VERSION 5.8 ;
BUSBITCHARS "[]" ;
DIVIDERCHAR "/" ;
UNITS
    DATABASE MICRONS 1000 ;
END UNITS

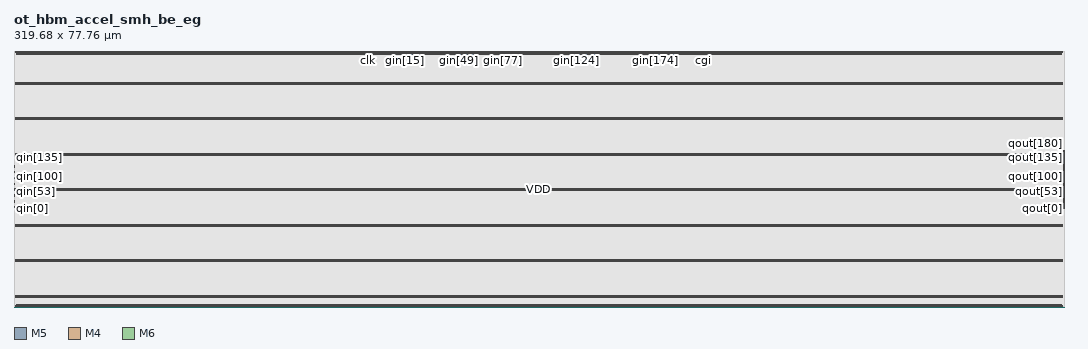
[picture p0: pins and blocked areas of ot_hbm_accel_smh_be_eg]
MACRO ot_hbm_accel_smh_be_eg
  FOREIGN ot_hbm_accel_smh_be_eg 0 0 ;
  CLASS BLOCK ;
  SIZE 319.68 BY 77.76 ;
  PIN cgi
    DIRECTION INPUT ;
    USE SIGNAL ;
    PORT
      LAYER M5 ;
        RECT  209.856 77.568 209.88 77.76 ;
    END
  END cgi
  PIN cgo
    DIRECTION OUTPUT ;
    USE SIGNAL ;
    PORT
      LAYER M5 ;
        RECT  210.336 77.568 210.36 77.76 ;
    END
  END cgo
  PIN clk
    DIRECTION INPUT ;
    USE SIGNAL ;
    PORT
      LAYER M5 ;
        RECT  107.856 77.568 107.88 77.76 ;
    END
  END clk
  PIN gin[0]
    DIRECTION INPUT ;
    USE SIGNAL ;
    PORT
      LAYER M5 ;
        RECT  111.84 77.568 111.864 77.76 ;
    END
  END gin[0]
  PIN gin[100]
    DIRECTION INPUT ;
    USE SIGNAL ;
    PORT
      LAYER M5 ;
        RECT  159.84 77.568 159.864 77.76 ;
    END
  END gin[100]
  PIN gin[101]
    DIRECTION INPUT ;
    USE SIGNAL ;
    PORT
      LAYER M5 ;
        RECT  160.32 77.568 160.344 77.76 ;
    END
  END gin[101]
  PIN gin[102]
    DIRECTION INPUT ;
    USE SIGNAL ;
    PORT
      LAYER M5 ;
        RECT  160.8 77.568 160.824 77.76 ;
    END
  END gin[102]
  PIN gin[103]
    DIRECTION INPUT ;
    USE SIGNAL ;
    PORT
      LAYER M5 ;
        RECT  161.28 77.568 161.304 77.76 ;
    END
  END gin[103]
  PIN gin[104]
    DIRECTION INPUT ;
    USE SIGNAL ;
    PORT
      LAYER M5 ;
        RECT  161.76 77.568 161.784 77.76 ;
    END
  END gin[104]
  PIN gin[105]
    DIRECTION INPUT ;
    USE SIGNAL ;
    PORT
      LAYER M5 ;
        RECT  162.24 77.568 162.264 77.76 ;
    END
  END gin[105]
  PIN gin[106]
    DIRECTION INPUT ;
    USE SIGNAL ;
    PORT
      LAYER M5 ;
        RECT  162.72 77.568 162.744 77.76 ;
    END
  END gin[106]
  PIN gin[107]
    DIRECTION INPUT ;
    USE SIGNAL ;
    PORT
      LAYER M5 ;
        RECT  163.2 77.568 163.224 77.76 ;
    END
  END gin[107]
  PIN gin[108]
    DIRECTION INPUT ;
    USE SIGNAL ;
    PORT
      LAYER M5 ;
        RECT  163.68 77.568 163.704 77.76 ;
    END
  END gin[108]
  PIN gin[109]
    DIRECTION INPUT ;
    USE SIGNAL ;
    PORT
      LAYER M5 ;
        RECT  164.16 77.568 164.184 77.76 ;
    END
  END gin[109]
  PIN gin[10]
    DIRECTION INPUT ;
    USE SIGNAL ;
    PORT
      LAYER M5 ;
        RECT  116.64 77.568 116.664 77.76 ;
    END
  END gin[10]
  PIN gin[110]
    DIRECTION INPUT ;
    USE SIGNAL ;
    PORT
      LAYER M5 ;
        RECT  164.64 77.568 164.664 77.76 ;
    END
  END gin[110]
  PIN gin[111]
    DIRECTION INPUT ;
    USE SIGNAL ;
    PORT
      LAYER M5 ;
        RECT  165.12 77.568 165.144 77.76 ;
    END
  END gin[111]
  PIN gin[112]
    DIRECTION INPUT ;
    USE SIGNAL ;
    PORT
      LAYER M5 ;
        RECT  165.6 77.568 165.624 77.76 ;
    END
  END gin[112]
  PIN gin[113]
    DIRECTION INPUT ;
    USE SIGNAL ;
    PORT
      LAYER M5 ;
        RECT  166.08 77.568 166.104 77.76 ;
    END
  END gin[113]
  PIN gin[114]
    DIRECTION INPUT ;
    USE SIGNAL ;
    PORT
      LAYER M5 ;
        RECT  166.56 77.568 166.584 77.76 ;
    END
  END gin[114]
  PIN gin[115]
    DIRECTION INPUT ;
    USE SIGNAL ;
    PORT
      LAYER M5 ;
        RECT  167.04 77.568 167.064 77.76 ;
    END
  END gin[115]
  PIN gin[116]
    DIRECTION INPUT ;
    USE SIGNAL ;
    PORT
      LAYER M5 ;
        RECT  167.52 77.568 167.544 77.76 ;
    END
  END gin[116]
  PIN gin[117]
    DIRECTION INPUT ;
    USE SIGNAL ;
    PORT
      LAYER M5 ;
        RECT  168 77.568 168.024 77.76 ;
    END
  END gin[117]
  PIN gin[118]
    DIRECTION INPUT ;
    USE SIGNAL ;
    PORT
      LAYER M5 ;
        RECT  168.48 77.568 168.504 77.76 ;
    END
  END gin[118]
  PIN gin[119]
    DIRECTION INPUT ;
    USE SIGNAL ;
    PORT
      LAYER M5 ;
        RECT  168.96 77.568 168.984 77.76 ;
    END
  END gin[119]
  PIN gin[11]
    DIRECTION INPUT ;
    USE SIGNAL ;
    PORT
      LAYER M5 ;
        RECT  117.12 77.568 117.144 77.76 ;
    END
  END gin[11]
  PIN gin[120]
    DIRECTION INPUT ;
    USE SIGNAL ;
    PORT
      LAYER M5 ;
        RECT  169.44 77.568 169.464 77.76 ;
    END
  END gin[120]
  PIN gin[121]
    DIRECTION INPUT ;
    USE SIGNAL ;
    PORT
      LAYER M5 ;
        RECT  169.92 77.568 169.944 77.76 ;
    END
  END gin[121]
  PIN gin[122]
    DIRECTION INPUT ;
    USE SIGNAL ;
    PORT
      LAYER M5 ;
        RECT  170.4 77.568 170.424 77.76 ;
    END
  END gin[122]
  PIN gin[123]
    DIRECTION INPUT ;
    USE SIGNAL ;
    PORT
      LAYER M5 ;
        RECT  170.88 77.568 170.904 77.76 ;
    END
  END gin[123]
  PIN gin[124]
    DIRECTION INPUT ;
    USE SIGNAL ;
    PORT
      LAYER M5 ;
        RECT  171.36 77.568 171.384 77.76 ;
    END
  END gin[124]
  PIN gin[125]
    DIRECTION INPUT ;
    USE SIGNAL ;
    PORT
      LAYER M5 ;
        RECT  171.84 77.568 171.864 77.76 ;
    END
  END gin[125]
  PIN gin[126]
    DIRECTION INPUT ;
    USE SIGNAL ;
    PORT
      LAYER M5 ;
        RECT  172.32 77.568 172.344 77.76 ;
    END
  END gin[126]
  PIN gin[127]
    DIRECTION INPUT ;
    USE SIGNAL ;
    PORT
      LAYER M5 ;
        RECT  172.8 77.568 172.824 77.76 ;
    END
  END gin[127]
  PIN gin[128]
    DIRECTION INPUT ;
    USE SIGNAL ;
    PORT
      LAYER M5 ;
        RECT  173.28 77.568 173.304 77.76 ;
    END
  END gin[128]
  PIN gin[129]
    DIRECTION INPUT ;
    USE SIGNAL ;
    PORT
      LAYER M5 ;
        RECT  173.76 77.568 173.784 77.76 ;
    END
  END gin[129]
  PIN gin[12]
    DIRECTION INPUT ;
    USE SIGNAL ;
    PORT
      LAYER M5 ;
        RECT  117.6 77.568 117.624 77.76 ;
    END
  END gin[12]
  PIN gin[130]
    DIRECTION INPUT ;
    USE SIGNAL ;
    PORT
      LAYER M5 ;
        RECT  174.24 77.568 174.264 77.76 ;
    END
  END gin[130]
  PIN gin[131]
    DIRECTION INPUT ;
    USE SIGNAL ;
    PORT
      LAYER M5 ;
        RECT  174.72 77.568 174.744 77.76 ;
    END
  END gin[131]
  PIN gin[132]
    DIRECTION INPUT ;
    USE SIGNAL ;
    PORT
      LAYER M5 ;
        RECT  175.2 77.568 175.224 77.76 ;
    END
  END gin[132]
  PIN gin[133]
    DIRECTION INPUT ;
    USE SIGNAL ;
    PORT
      LAYER M5 ;
        RECT  175.68 77.568 175.704 77.76 ;
    END
  END gin[133]
  PIN gin[134]
    DIRECTION INPUT ;
    USE SIGNAL ;
    PORT
      LAYER M5 ;
        RECT  176.16 77.568 176.184 77.76 ;
    END
  END gin[134]
  PIN gin[135]
    DIRECTION INPUT ;
    USE SIGNAL ;
    PORT
      LAYER M5 ;
        RECT  176.64 77.568 176.664 77.76 ;
    END
  END gin[135]
  PIN gin[136]
    DIRECTION INPUT ;
    USE SIGNAL ;
    PORT
      LAYER M5 ;
        RECT  177.12 77.568 177.144 77.76 ;
    END
  END gin[136]
  PIN gin[137]
    DIRECTION INPUT ;
    USE SIGNAL ;
    PORT
      LAYER M5 ;
        RECT  177.6 77.568 177.624 77.76 ;
    END
  END gin[137]
  PIN gin[138]
    DIRECTION INPUT ;
    USE SIGNAL ;
    PORT
      LAYER M5 ;
        RECT  178.08 77.568 178.104 77.76 ;
    END
  END gin[138]
  PIN gin[139]
    DIRECTION INPUT ;
    USE SIGNAL ;
    PORT
      LAYER M5 ;
        RECT  178.56 77.568 178.584 77.76 ;
    END
  END gin[139]
  PIN gin[13]
    DIRECTION INPUT ;
    USE SIGNAL ;
    PORT
      LAYER M5 ;
        RECT  118.08 77.568 118.104 77.76 ;
    END
  END gin[13]
  PIN gin[140]
    DIRECTION INPUT ;
    USE SIGNAL ;
    PORT
      LAYER M5 ;
        RECT  179.04 77.568 179.064 77.76 ;
    END
  END gin[140]
  PIN gin[141]
    DIRECTION INPUT ;
    USE SIGNAL ;
    PORT
      LAYER M5 ;
        RECT  179.52 77.568 179.544 77.76 ;
    END
  END gin[141]
  PIN gin[142]
    DIRECTION INPUT ;
    USE SIGNAL ;
    PORT
      LAYER M5 ;
        RECT  180 77.568 180.024 77.76 ;
    END
  END gin[142]
  PIN gin[143]
    DIRECTION INPUT ;
    USE SIGNAL ;
    PORT
      LAYER M5 ;
        RECT  180.48 77.568 180.504 77.76 ;
    END
  END gin[143]
  PIN gin[144]
    DIRECTION INPUT ;
    USE SIGNAL ;
    PORT
      LAYER M5 ;
        RECT  180.96 77.568 180.984 77.76 ;
    END
  END gin[144]
  PIN gin[145]
    DIRECTION INPUT ;
    USE SIGNAL ;
    PORT
      LAYER M5 ;
        RECT  181.44 77.568 181.464 77.76 ;
    END
  END gin[145]
  PIN gin[146]
    DIRECTION INPUT ;
    USE SIGNAL ;
    PORT
      LAYER M5 ;
        RECT  181.92 77.568 181.944 77.76 ;
    END
  END gin[146]
  PIN gin[147]
    DIRECTION INPUT ;
    USE SIGNAL ;
    PORT
      LAYER M5 ;
        RECT  182.4 77.568 182.424 77.76 ;
    END
  END gin[147]
  PIN gin[148]
    DIRECTION INPUT ;
    USE SIGNAL ;
    PORT
      LAYER M5 ;
        RECT  182.88 77.568 182.904 77.76 ;
    END
  END gin[148]
  PIN gin[149]
    DIRECTION INPUT ;
    USE SIGNAL ;
    PORT
      LAYER M5 ;
        RECT  183.36 77.568 183.384 77.76 ;
    END
  END gin[149]
  PIN gin[14]
    DIRECTION INPUT ;
    USE SIGNAL ;
    PORT
      LAYER M5 ;
        RECT  118.56 77.568 118.584 77.76 ;
    END
  END gin[14]
  PIN gin[150]
    DIRECTION INPUT ;
    USE SIGNAL ;
    PORT
      LAYER M5 ;
        RECT  183.84 77.568 183.864 77.76 ;
    END
  END gin[150]
  PIN gin[151]
    DIRECTION INPUT ;
    USE SIGNAL ;
    PORT
      LAYER M5 ;
        RECT  184.32 77.568 184.344 77.76 ;
    END
  END gin[151]
  PIN gin[152]
    DIRECTION INPUT ;
    USE SIGNAL ;
    PORT
      LAYER M5 ;
        RECT  184.8 77.568 184.824 77.76 ;
    END
  END gin[152]
  PIN gin[153]
    DIRECTION INPUT ;
    USE SIGNAL ;
    PORT
      LAYER M5 ;
        RECT  185.28 77.568 185.304 77.76 ;
    END
  END gin[153]
  PIN gin[154]
    DIRECTION INPUT ;
    USE SIGNAL ;
    PORT
      LAYER M5 ;
        RECT  185.76 77.568 185.784 77.76 ;
    END
  END gin[154]
  PIN gin[155]
    DIRECTION INPUT ;
    USE SIGNAL ;
    PORT
      LAYER M5 ;
        RECT  186.24 77.568 186.264 77.76 ;
    END
  END gin[155]
  PIN gin[156]
    DIRECTION INPUT ;
    USE SIGNAL ;
    PORT
      LAYER M5 ;
        RECT  186.72 77.568 186.744 77.76 ;
    END
  END gin[156]
  PIN gin[157]
    DIRECTION INPUT ;
    USE SIGNAL ;
    PORT
      LAYER M5 ;
        RECT  187.2 77.568 187.224 77.76 ;
    END
  END gin[157]
  PIN gin[158]
    DIRECTION INPUT ;
    USE SIGNAL ;
    PORT
      LAYER M5 ;
        RECT  187.68 77.568 187.704 77.76 ;
    END
  END gin[158]
  PIN gin[159]
    DIRECTION INPUT ;
    USE SIGNAL ;
    PORT
      LAYER M5 ;
        RECT  188.16 77.568 188.184 77.76 ;
    END
  END gin[159]
  PIN gin[15]
    DIRECTION INPUT ;
    USE SIGNAL ;
    PORT
      LAYER M5 ;
        RECT  119.04 77.568 119.064 77.76 ;
    END
  END gin[15]
  PIN gin[160]
    DIRECTION INPUT ;
    USE SIGNAL ;
    PORT
      LAYER M5 ;
        RECT  188.64 77.568 188.664 77.76 ;
    END
  END gin[160]
  PIN gin[161]
    DIRECTION INPUT ;
    USE SIGNAL ;
    PORT
      LAYER M5 ;
        RECT  189.12 77.568 189.144 77.76 ;
    END
  END gin[161]
  PIN gin[162]
    DIRECTION INPUT ;
    USE SIGNAL ;
    PORT
      LAYER M5 ;
        RECT  189.6 77.568 189.624 77.76 ;
    END
  END gin[162]
  PIN gin[163]
    DIRECTION INPUT ;
    USE SIGNAL ;
    PORT
      LAYER M5 ;
        RECT  190.08 77.568 190.104 77.76 ;
    END
  END gin[163]
  PIN gin[164]
    DIRECTION INPUT ;
    USE SIGNAL ;
    PORT
      LAYER M5 ;
        RECT  190.56 77.568 190.584 77.76 ;
    END
  END gin[164]
  PIN gin[165]
    DIRECTION INPUT ;
    USE SIGNAL ;
    PORT
      LAYER M5 ;
        RECT  191.04 77.568 191.064 77.76 ;
    END
  END gin[165]
  PIN gin[166]
    DIRECTION INPUT ;
    USE SIGNAL ;
    PORT
      LAYER M5 ;
        RECT  191.52 77.568 191.544 77.76 ;
    END
  END gin[166]
  PIN gin[167]
    DIRECTION INPUT ;
    USE SIGNAL ;
    PORT
      LAYER M5 ;
        RECT  192 77.568 192.024 77.76 ;
    END
  END gin[167]
  PIN gin[168]
    DIRECTION INPUT ;
    USE SIGNAL ;
    PORT
      LAYER M5 ;
        RECT  192.48 77.568 192.504 77.76 ;
    END
  END gin[168]
  PIN gin[169]
    DIRECTION INPUT ;
    USE SIGNAL ;
    PORT
      LAYER M5 ;
        RECT  192.96 77.568 192.984 77.76 ;
    END
  END gin[169]
  PIN gin[16]
    DIRECTION INPUT ;
    USE SIGNAL ;
    PORT
      LAYER M5 ;
        RECT  119.52 77.568 119.544 77.76 ;
    END
  END gin[16]
  PIN gin[170]
    DIRECTION INPUT ;
    USE SIGNAL ;
    PORT
      LAYER M5 ;
        RECT  193.44 77.568 193.464 77.76 ;
    END
  END gin[170]
  PIN gin[171]
    DIRECTION INPUT ;
    USE SIGNAL ;
    PORT
      LAYER M5 ;
        RECT  193.92 77.568 193.944 77.76 ;
    END
  END gin[171]
  PIN gin[172]
    DIRECTION INPUT ;
    USE SIGNAL ;
    PORT
      LAYER M5 ;
        RECT  194.4 77.568 194.424 77.76 ;
    END
  END gin[172]
  PIN gin[173]
    DIRECTION INPUT ;
    USE SIGNAL ;
    PORT
      LAYER M5 ;
        RECT  194.88 77.568 194.904 77.76 ;
    END
  END gin[173]
  PIN gin[174]
    DIRECTION INPUT ;
    USE SIGNAL ;
    PORT
      LAYER M5 ;
        RECT  195.36 77.568 195.384 77.76 ;
    END
  END gin[174]
  PIN gin[175]
    DIRECTION INPUT ;
    USE SIGNAL ;
    PORT
      LAYER M5 ;
        RECT  195.84 77.568 195.864 77.76 ;
    END
  END gin[175]
  PIN gin[176]
    DIRECTION INPUT ;
    USE SIGNAL ;
    PORT
      LAYER M5 ;
        RECT  196.32 77.568 196.344 77.76 ;
    END
  END gin[176]
  PIN gin[177]
    DIRECTION INPUT ;
    USE SIGNAL ;
    PORT
      LAYER M5 ;
        RECT  196.8 77.568 196.824 77.76 ;
    END
  END gin[177]
  PIN gin[178]
    DIRECTION INPUT ;
    USE SIGNAL ;
    PORT
      LAYER M5 ;
        RECT  197.28 77.568 197.304 77.76 ;
    END
  END gin[178]
  PIN gin[179]
    DIRECTION INPUT ;
    USE SIGNAL ;
    PORT
      LAYER M5 ;
        RECT  197.76 77.568 197.784 77.76 ;
    END
  END gin[179]
  PIN gin[17]
    DIRECTION INPUT ;
    USE SIGNAL ;
    PORT
      LAYER M5 ;
        RECT  120 77.568 120.024 77.76 ;
    END
  END gin[17]
  PIN gin[180]
    DIRECTION INPUT ;
    USE SIGNAL ;
    PORT
      LAYER M5 ;
        RECT  198.24 77.568 198.264 77.76 ;
    END
  END gin[180]
  PIN gin[181]
    DIRECTION INPUT ;
    USE SIGNAL ;
    PORT
      LAYER M5 ;
        RECT  198.72 77.568 198.744 77.76 ;
    END
  END gin[181]
  PIN gin[182]
    DIRECTION INPUT ;
    USE SIGNAL ;
    PORT
      LAYER M5 ;
        RECT  199.2 77.568 199.224 77.76 ;
    END
  END gin[182]
  PIN gin[183]
    DIRECTION INPUT ;
    USE SIGNAL ;
    PORT
      LAYER M5 ;
        RECT  199.68 77.568 199.704 77.76 ;
    END
  END gin[183]
  PIN gin[184]
    DIRECTION INPUT ;
    USE SIGNAL ;
    PORT
      LAYER M5 ;
        RECT  200.16 77.568 200.184 77.76 ;
    END
  END gin[184]
  PIN gin[185]
    DIRECTION INPUT ;
    USE SIGNAL ;
    PORT
      LAYER M5 ;
        RECT  200.64 77.568 200.664 77.76 ;
    END
  END gin[185]
  PIN gin[186]
    DIRECTION INPUT ;
    USE SIGNAL ;
    PORT
      LAYER M5 ;
        RECT  201.12 77.568 201.144 77.76 ;
    END
  END gin[186]
  PIN gin[187]
    DIRECTION INPUT ;
    USE SIGNAL ;
    PORT
      LAYER M5 ;
        RECT  201.6 77.568 201.624 77.76 ;
    END
  END gin[187]
  PIN gin[188]
    DIRECTION INPUT ;
    USE SIGNAL ;
    PORT
      LAYER M5 ;
        RECT  202.08 77.568 202.104 77.76 ;
    END
  END gin[188]
  PIN gin[189]
    DIRECTION INPUT ;
    USE SIGNAL ;
    PORT
      LAYER M5 ;
        RECT  202.56 77.568 202.584 77.76 ;
    END
  END gin[189]
  PIN gin[18]
    DIRECTION INPUT ;
    USE SIGNAL ;
    PORT
      LAYER M5 ;
        RECT  120.48 77.568 120.504 77.76 ;
    END
  END gin[18]
  PIN gin[190]
    DIRECTION INPUT ;
    USE SIGNAL ;
    PORT
      LAYER M5 ;
        RECT  203.04 77.568 203.064 77.76 ;
    END
  END gin[190]
  PIN gin[191]
    DIRECTION INPUT ;
    USE SIGNAL ;
    PORT
      LAYER M5 ;
        RECT  203.52 77.568 203.544 77.76 ;
    END
  END gin[191]
  PIN gin[192]
    DIRECTION INPUT ;
    USE SIGNAL ;
    PORT
      LAYER M5 ;
        RECT  204 77.568 204.024 77.76 ;
    END
  END gin[192]
  PIN gin[193]
    DIRECTION INPUT ;
    USE SIGNAL ;
    PORT
      LAYER M5 ;
        RECT  204.48 77.568 204.504 77.76 ;
    END
  END gin[193]
  PIN gin[194]
    DIRECTION INPUT ;
    USE SIGNAL ;
    PORT
      LAYER M5 ;
        RECT  204.96 77.568 204.984 77.76 ;
    END
  END gin[194]
  PIN gin[195]
    DIRECTION INPUT ;
    USE SIGNAL ;
    PORT
      LAYER M5 ;
        RECT  205.44 77.568 205.464 77.76 ;
    END
  END gin[195]
  PIN gin[196]
    DIRECTION INPUT ;
    USE SIGNAL ;
    PORT
      LAYER M5 ;
        RECT  205.92 77.568 205.944 77.76 ;
    END
  END gin[196]
  PIN gin[197]
    DIRECTION INPUT ;
    USE SIGNAL ;
    PORT
      LAYER M5 ;
        RECT  206.4 77.568 206.424 77.76 ;
    END
  END gin[197]
  PIN gin[198]
    DIRECTION INPUT ;
    USE SIGNAL ;
    PORT
      LAYER M5 ;
        RECT  206.88 77.568 206.904 77.76 ;
    END
  END gin[198]
  PIN gin[199]
    DIRECTION INPUT ;
    USE SIGNAL ;
    PORT
      LAYER M5 ;
        RECT  207.36 77.568 207.384 77.76 ;
    END
  END gin[199]
  PIN gin[19]
    DIRECTION INPUT ;
    USE SIGNAL ;
    PORT
      LAYER M5 ;
        RECT  120.96 77.568 120.984 77.76 ;
    END
  END gin[19]
  PIN gin[1]
    DIRECTION INPUT ;
    USE SIGNAL ;
    PORT
      LAYER M5 ;
        RECT  112.32 77.568 112.344 77.76 ;
    END
  END gin[1]
  PIN gin[20]
    DIRECTION INPUT ;
    USE SIGNAL ;
    PORT
      LAYER M5 ;
        RECT  121.44 77.568 121.464 77.76 ;
    END
  END gin[20]
  PIN gin[21]
    DIRECTION INPUT ;
    USE SIGNAL ;
    PORT
      LAYER M5 ;
        RECT  121.92 77.568 121.944 77.76 ;
    END
  END gin[21]
  PIN gin[22]
    DIRECTION INPUT ;
    USE SIGNAL ;
    PORT
      LAYER M5 ;
        RECT  122.4 77.568 122.424 77.76 ;
    END
  END gin[22]
  PIN gin[23]
    DIRECTION INPUT ;
    USE SIGNAL ;
    PORT
      LAYER M5 ;
        RECT  122.88 77.568 122.904 77.76 ;
    END
  END gin[23]
  PIN gin[24]
    DIRECTION INPUT ;
    USE SIGNAL ;
    PORT
      LAYER M5 ;
        RECT  123.36 77.568 123.384 77.76 ;
    END
  END gin[24]
  PIN gin[25]
    DIRECTION INPUT ;
    USE SIGNAL ;
    PORT
      LAYER M5 ;
        RECT  123.84 77.568 123.864 77.76 ;
    END
  END gin[25]
  PIN gin[26]
    DIRECTION INPUT ;
    USE SIGNAL ;
    PORT
      LAYER M5 ;
        RECT  124.32 77.568 124.344 77.76 ;
    END
  END gin[26]
  PIN gin[27]
    DIRECTION INPUT ;
    USE SIGNAL ;
    PORT
      LAYER M5 ;
        RECT  124.8 77.568 124.824 77.76 ;
    END
  END gin[27]
  PIN gin[28]
    DIRECTION INPUT ;
    USE SIGNAL ;
    PORT
      LAYER M5 ;
        RECT  125.28 77.568 125.304 77.76 ;
    END
  END gin[28]
  PIN gin[29]
    DIRECTION INPUT ;
    USE SIGNAL ;
    PORT
      LAYER M5 ;
        RECT  125.76 77.568 125.784 77.76 ;
    END
  END gin[29]
  PIN gin[2]
    DIRECTION INPUT ;
    USE SIGNAL ;
    PORT
      LAYER M5 ;
        RECT  112.8 77.568 112.824 77.76 ;
    END
  END gin[2]
  PIN gin[30]
    DIRECTION INPUT ;
    USE SIGNAL ;
    PORT
      LAYER M5 ;
        RECT  126.24 77.568 126.264 77.76 ;
    END
  END gin[30]
  PIN gin[31]
    DIRECTION INPUT ;
    USE SIGNAL ;
    PORT
      LAYER M5 ;
        RECT  126.72 77.568 126.744 77.76 ;
    END
  END gin[31]
  PIN gin[32]
    DIRECTION INPUT ;
    USE SIGNAL ;
    PORT
      LAYER M5 ;
        RECT  127.2 77.568 127.224 77.76 ;
    END
  END gin[32]
  PIN gin[33]
    DIRECTION INPUT ;
    USE SIGNAL ;
    PORT
      LAYER M5 ;
        RECT  127.68 77.568 127.704 77.76 ;
    END
  END gin[33]
  PIN gin[34]
    DIRECTION INPUT ;
    USE SIGNAL ;
    PORT
      LAYER M5 ;
        RECT  128.16 77.568 128.184 77.76 ;
    END
  END gin[34]
  PIN gin[35]
    DIRECTION INPUT ;
    USE SIGNAL ;
    PORT
      LAYER M5 ;
        RECT  128.64 77.568 128.664 77.76 ;
    END
  END gin[35]
  PIN gin[36]
    DIRECTION INPUT ;
    USE SIGNAL ;
    PORT
      LAYER M5 ;
        RECT  129.12 77.568 129.144 77.76 ;
    END
  END gin[36]
  PIN gin[37]
    DIRECTION INPUT ;
    USE SIGNAL ;
    PORT
      LAYER M5 ;
        RECT  129.6 77.568 129.624 77.76 ;
    END
  END gin[37]
  PIN gin[38]
    DIRECTION INPUT ;
    USE SIGNAL ;
    PORT
      LAYER M5 ;
        RECT  130.08 77.568 130.104 77.76 ;
    END
  END gin[38]
  PIN gin[39]
    DIRECTION INPUT ;
    USE SIGNAL ;
    PORT
      LAYER M5 ;
        RECT  130.56 77.568 130.584 77.76 ;
    END
  END gin[39]
  PIN gin[3]
    DIRECTION INPUT ;
    USE SIGNAL ;
    PORT
      LAYER M5 ;
        RECT  113.28 77.568 113.304 77.76 ;
    END
  END gin[3]
  PIN gin[40]
    DIRECTION INPUT ;
    USE SIGNAL ;
    PORT
      LAYER M5 ;
        RECT  131.04 77.568 131.064 77.76 ;
    END
  END gin[40]
  PIN gin[41]
    DIRECTION INPUT ;
    USE SIGNAL ;
    PORT
      LAYER M5 ;
        RECT  131.52 77.568 131.544 77.76 ;
    END
  END gin[41]
  PIN gin[42]
    DIRECTION INPUT ;
    USE SIGNAL ;
    PORT
      LAYER M5 ;
        RECT  132 77.568 132.024 77.76 ;
    END
  END gin[42]
  PIN gin[43]
    DIRECTION INPUT ;
    USE SIGNAL ;
    PORT
      LAYER M5 ;
        RECT  132.48 77.568 132.504 77.76 ;
    END
  END gin[43]
  PIN gin[44]
    DIRECTION INPUT ;
    USE SIGNAL ;
    PORT
      LAYER M5 ;
        RECT  132.96 77.568 132.984 77.76 ;
    END
  END gin[44]
  PIN gin[45]
    DIRECTION INPUT ;
    USE SIGNAL ;
    PORT
      LAYER M5 ;
        RECT  133.44 77.568 133.464 77.76 ;
    END
  END gin[45]
  PIN gin[46]
    DIRECTION INPUT ;
    USE SIGNAL ;
    PORT
      LAYER M5 ;
        RECT  133.92 77.568 133.944 77.76 ;
    END
  END gin[46]
  PIN gin[47]
    DIRECTION INPUT ;
    USE SIGNAL ;
    PORT
      LAYER M5 ;
        RECT  134.4 77.568 134.424 77.76 ;
    END
  END gin[47]
  PIN gin[48]
    DIRECTION INPUT ;
    USE SIGNAL ;
    PORT
      LAYER M5 ;
        RECT  134.88 77.568 134.904 77.76 ;
    END
  END gin[48]
  PIN gin[49]
    DIRECTION INPUT ;
    USE SIGNAL ;
    PORT
      LAYER M5 ;
        RECT  135.36 77.568 135.384 77.76 ;
    END
  END gin[49]
  PIN gin[4]
    DIRECTION INPUT ;
    USE SIGNAL ;
    PORT
      LAYER M5 ;
        RECT  113.76 77.568 113.784 77.76 ;
    END
  END gin[4]
  PIN gin[50]
    DIRECTION INPUT ;
    USE SIGNAL ;
    PORT
      LAYER M5 ;
        RECT  135.84 77.568 135.864 77.76 ;
    END
  END gin[50]
  PIN gin[51]
    DIRECTION INPUT ;
    USE SIGNAL ;
    PORT
      LAYER M5 ;
        RECT  136.32 77.568 136.344 77.76 ;
    END
  END gin[51]
  PIN gin[52]
    DIRECTION INPUT ;
    USE SIGNAL ;
    PORT
      LAYER M5 ;
        RECT  136.8 77.568 136.824 77.76 ;
    END
  END gin[52]
  PIN gin[53]
    DIRECTION INPUT ;
    USE SIGNAL ;
    PORT
      LAYER M5 ;
        RECT  137.28 77.568 137.304 77.76 ;
    END
  END gin[53]
  PIN gin[54]
    DIRECTION INPUT ;
    USE SIGNAL ;
    PORT
      LAYER M5 ;
        RECT  137.76 77.568 137.784 77.76 ;
    END
  END gin[54]
  PIN gin[55]
    DIRECTION INPUT ;
    USE SIGNAL ;
    PORT
      LAYER M5 ;
        RECT  138.24 77.568 138.264 77.76 ;
    END
  END gin[55]
  PIN gin[56]
    DIRECTION INPUT ;
    USE SIGNAL ;
    PORT
      LAYER M5 ;
        RECT  138.72 77.568 138.744 77.76 ;
    END
  END gin[56]
  PIN gin[57]
    DIRECTION INPUT ;
    USE SIGNAL ;
    PORT
      LAYER M5 ;
        RECT  139.2 77.568 139.224 77.76 ;
    END
  END gin[57]
  PIN gin[58]
    DIRECTION INPUT ;
    USE SIGNAL ;
    PORT
      LAYER M5 ;
        RECT  139.68 77.568 139.704 77.76 ;
    END
  END gin[58]
  PIN gin[59]
    DIRECTION INPUT ;
    USE SIGNAL ;
    PORT
      LAYER M5 ;
        RECT  140.16 77.568 140.184 77.76 ;
    END
  END gin[59]
  PIN gin[5]
    DIRECTION INPUT ;
    USE SIGNAL ;
    PORT
      LAYER M5 ;
        RECT  114.24 77.568 114.264 77.76 ;
    END
  END gin[5]
  PIN gin[60]
    DIRECTION INPUT ;
    USE SIGNAL ;
    PORT
      LAYER M5 ;
        RECT  140.64 77.568 140.664 77.76 ;
    END
  END gin[60]
  PIN gin[61]
    DIRECTION INPUT ;
    USE SIGNAL ;
    PORT
      LAYER M5 ;
        RECT  141.12 77.568 141.144 77.76 ;
    END
  END gin[61]
  PIN gin[62]
    DIRECTION INPUT ;
    USE SIGNAL ;
    PORT
      LAYER M5 ;
        RECT  141.6 77.568 141.624 77.76 ;
    END
  END gin[62]
  PIN gin[63]
    DIRECTION INPUT ;
    USE SIGNAL ;
    PORT
      LAYER M5 ;
        RECT  142.08 77.568 142.104 77.76 ;
    END
  END gin[63]
  PIN gin[64]
    DIRECTION INPUT ;
    USE SIGNAL ;
    PORT
      LAYER M5 ;
        RECT  142.56 77.568 142.584 77.76 ;
    END
  END gin[64]
  PIN gin[65]
    DIRECTION INPUT ;
    USE SIGNAL ;
    PORT
      LAYER M5 ;
        RECT  143.04 77.568 143.064 77.76 ;
    END
  END gin[65]
  PIN gin[66]
    DIRECTION INPUT ;
    USE SIGNAL ;
    PORT
      LAYER M5 ;
        RECT  143.52 77.568 143.544 77.76 ;
    END
  END gin[66]
  PIN gin[67]
    DIRECTION INPUT ;
    USE SIGNAL ;
    PORT
      LAYER M5 ;
        RECT  144 77.568 144.024 77.76 ;
    END
  END gin[67]
  PIN gin[68]
    DIRECTION INPUT ;
    USE SIGNAL ;
    PORT
      LAYER M5 ;
        RECT  144.48 77.568 144.504 77.76 ;
    END
  END gin[68]
  PIN gin[69]
    DIRECTION INPUT ;
    USE SIGNAL ;
    PORT
      LAYER M5 ;
        RECT  144.96 77.568 144.984 77.76 ;
    END
  END gin[69]
  PIN gin[6]
    DIRECTION INPUT ;
    USE SIGNAL ;
    PORT
      LAYER M5 ;
        RECT  114.72 77.568 114.744 77.76 ;
    END
  END gin[6]
  PIN gin[70]
    DIRECTION INPUT ;
    USE SIGNAL ;
    PORT
      LAYER M5 ;
        RECT  145.44 77.568 145.464 77.76 ;
    END
  END gin[70]
  PIN gin[71]
    DIRECTION INPUT ;
    USE SIGNAL ;
    PORT
      LAYER M5 ;
        RECT  145.92 77.568 145.944 77.76 ;
    END
  END gin[71]
  PIN gin[72]
    DIRECTION INPUT ;
    USE SIGNAL ;
    PORT
      LAYER M5 ;
        RECT  146.4 77.568 146.424 77.76 ;
    END
  END gin[72]
  PIN gin[73]
    DIRECTION INPUT ;
    USE SIGNAL ;
    PORT
      LAYER M5 ;
        RECT  146.88 77.568 146.904 77.76 ;
    END
  END gin[73]
  PIN gin[74]
    DIRECTION INPUT ;
    USE SIGNAL ;
    PORT
      LAYER M5 ;
        RECT  147.36 77.568 147.384 77.76 ;
    END
  END gin[74]
  PIN gin[75]
    DIRECTION INPUT ;
    USE SIGNAL ;
    PORT
      LAYER M5 ;
        RECT  147.84 77.568 147.864 77.76 ;
    END
  END gin[75]
  PIN gin[76]
    DIRECTION INPUT ;
    USE SIGNAL ;
    PORT
      LAYER M5 ;
        RECT  148.32 77.568 148.344 77.76 ;
    END
  END gin[76]
  PIN gin[77]
    DIRECTION INPUT ;
    USE SIGNAL ;
    PORT
      LAYER M5 ;
        RECT  148.8 77.568 148.824 77.76 ;
    END
  END gin[77]
  PIN gin[78]
    DIRECTION INPUT ;
    USE SIGNAL ;
    PORT
      LAYER M5 ;
        RECT  149.28 77.568 149.304 77.76 ;
    END
  END gin[78]
  PIN gin[79]
    DIRECTION INPUT ;
    USE SIGNAL ;
    PORT
      LAYER M5 ;
        RECT  149.76 77.568 149.784 77.76 ;
    END
  END gin[79]
  PIN gin[7]
    DIRECTION INPUT ;
    USE SIGNAL ;
    PORT
      LAYER M5 ;
        RECT  115.2 77.568 115.224 77.76 ;
    END
  END gin[7]
  PIN gin[80]
    DIRECTION INPUT ;
    USE SIGNAL ;
    PORT
      LAYER M5 ;
        RECT  150.24 77.568 150.264 77.76 ;
    END
  END gin[80]
  PIN gin[81]
    DIRECTION INPUT ;
    USE SIGNAL ;
    PORT
      LAYER M5 ;
        RECT  150.72 77.568 150.744 77.76 ;
    END
  END gin[81]
  PIN gin[82]
    DIRECTION INPUT ;
    USE SIGNAL ;
    PORT
      LAYER M5 ;
        RECT  151.2 77.568 151.224 77.76 ;
    END
  END gin[82]
  PIN gin[83]
    DIRECTION INPUT ;
    USE SIGNAL ;
    PORT
      LAYER M5 ;
        RECT  151.68 77.568 151.704 77.76 ;
    END
  END gin[83]
  PIN gin[84]
    DIRECTION INPUT ;
    USE SIGNAL ;
    PORT
      LAYER M5 ;
        RECT  152.16 77.568 152.184 77.76 ;
    END
  END gin[84]
  PIN gin[85]
    DIRECTION INPUT ;
    USE SIGNAL ;
    PORT
      LAYER M5 ;
        RECT  152.64 77.568 152.664 77.76 ;
    END
  END gin[85]
  PIN gin[86]
    DIRECTION INPUT ;
    USE SIGNAL ;
    PORT
      LAYER M5 ;
        RECT  153.12 77.568 153.144 77.76 ;
    END
  END gin[86]
  PIN gin[87]
    DIRECTION INPUT ;
    USE SIGNAL ;
    PORT
      LAYER M5 ;
        RECT  153.6 77.568 153.624 77.76 ;
    END
  END gin[87]
  PIN gin[88]
    DIRECTION INPUT ;
    USE SIGNAL ;
    PORT
      LAYER M5 ;
        RECT  154.08 77.568 154.104 77.76 ;
    END
  END gin[88]
  PIN gin[89]
    DIRECTION INPUT ;
    USE SIGNAL ;
    PORT
      LAYER M5 ;
        RECT  154.56 77.568 154.584 77.76 ;
    END
  END gin[89]
  PIN gin[8]
    DIRECTION INPUT ;
    USE SIGNAL ;
    PORT
      LAYER M5 ;
        RECT  115.68 77.568 115.704 77.76 ;
    END
  END gin[8]
  PIN gin[90]
    DIRECTION INPUT ;
    USE SIGNAL ;
    PORT
      LAYER M5 ;
        RECT  155.04 77.568 155.064 77.76 ;
    END
  END gin[90]
  PIN gin[91]
    DIRECTION INPUT ;
    USE SIGNAL ;
    PORT
      LAYER M5 ;
        RECT  155.52 77.568 155.544 77.76 ;
    END
  END gin[91]
  PIN gin[92]
    DIRECTION INPUT ;
    USE SIGNAL ;
    PORT
      LAYER M5 ;
        RECT  156 77.568 156.024 77.76 ;
    END
  END gin[92]
  PIN gin[93]
    DIRECTION INPUT ;
    USE SIGNAL ;
    PORT
      LAYER M5 ;
        RECT  156.48 77.568 156.504 77.76 ;
    END
  END gin[93]
  PIN gin[94]
    DIRECTION INPUT ;
    USE SIGNAL ;
    PORT
      LAYER M5 ;
        RECT  156.96 77.568 156.984 77.76 ;
    END
  END gin[94]
  PIN gin[95]
    DIRECTION INPUT ;
    USE SIGNAL ;
    PORT
      LAYER M5 ;
        RECT  157.44 77.568 157.464 77.76 ;
    END
  END gin[95]
  PIN gin[96]
    DIRECTION INPUT ;
    USE SIGNAL ;
    PORT
      LAYER M5 ;
        RECT  157.92 77.568 157.944 77.76 ;
    END
  END gin[96]
  PIN gin[97]
    DIRECTION INPUT ;
    USE SIGNAL ;
    PORT
      LAYER M5 ;
        RECT  158.4 77.568 158.424 77.76 ;
    END
  END gin[97]
  PIN gin[98]
    DIRECTION INPUT ;
    USE SIGNAL ;
    PORT
      LAYER M5 ;
        RECT  158.88 77.568 158.904 77.76 ;
    END
  END gin[98]
  PIN gin[99]
    DIRECTION INPUT ;
    USE SIGNAL ;
    PORT
      LAYER M5 ;
        RECT  159.36 77.568 159.384 77.76 ;
    END
  END gin[99]
  PIN gin[9]
    DIRECTION INPUT ;
    USE SIGNAL ;
    PORT
      LAYER M5 ;
        RECT  116.16 77.568 116.184 77.76 ;
    END
  END gin[9]
  PIN qin[0]
    DIRECTION INPUT ;
    USE SIGNAL ;
    PORT
      LAYER M4 ;
        RECT  0 30.048 0.192 30.072 ;
    END
  END qin[0]
  PIN qin[100]
    DIRECTION INPUT ;
    USE SIGNAL ;
    PORT
      LAYER M4 ;
        RECT  0 39.648 0.192 39.672 ;
    END
  END qin[100]
  PIN qin[101]
    DIRECTION INPUT ;
    USE SIGNAL ;
    PORT
      LAYER M4 ;
        RECT  0 39.744 0.192 39.768 ;
    END
  END qin[101]
  PIN qin[102]
    DIRECTION INPUT ;
    USE SIGNAL ;
    PORT
      LAYER M4 ;
        RECT  0 39.84 0.192 39.864 ;
    END
  END qin[102]
  PIN qin[103]
    DIRECTION INPUT ;
    USE SIGNAL ;
    PORT
      LAYER M4 ;
        RECT  0 39.936 0.192 39.96 ;
    END
  END qin[103]
  PIN qin[104]
    DIRECTION INPUT ;
    USE SIGNAL ;
    PORT
      LAYER M4 ;
        RECT  0 40.032 0.192 40.056 ;
    END
  END qin[104]
  PIN qin[105]
    DIRECTION INPUT ;
    USE SIGNAL ;
    PORT
      LAYER M4 ;
        RECT  0 40.128 0.192 40.152 ;
    END
  END qin[105]
  PIN qin[106]
    DIRECTION INPUT ;
    USE SIGNAL ;
    PORT
      LAYER M4 ;
        RECT  0 40.224 0.192 40.248 ;
    END
  END qin[106]
  PIN qin[107]
    DIRECTION INPUT ;
    USE SIGNAL ;
    PORT
      LAYER M4 ;
        RECT  0 40.32 0.192 40.344 ;
    END
  END qin[107]
  PIN qin[108]
    DIRECTION INPUT ;
    USE SIGNAL ;
    PORT
      LAYER M4 ;
        RECT  0 40.416 0.192 40.44 ;
    END
  END qin[108]
  PIN qin[109]
    DIRECTION INPUT ;
    USE SIGNAL ;
    PORT
      LAYER M4 ;
        RECT  0 40.512 0.192 40.536 ;
    END
  END qin[109]
  PIN qin[10]
    DIRECTION INPUT ;
    USE SIGNAL ;
    PORT
      LAYER M4 ;
        RECT  0 31.008 0.192 31.032 ;
    END
  END qin[10]
  PIN qin[110]
    DIRECTION INPUT ;
    USE SIGNAL ;
    PORT
      LAYER M4 ;
        RECT  0 40.608 0.192 40.632 ;
    END
  END qin[110]
  PIN qin[111]
    DIRECTION INPUT ;
    USE SIGNAL ;
    PORT
      LAYER M4 ;
        RECT  0 40.704 0.192 40.728 ;
    END
  END qin[111]
  PIN qin[112]
    DIRECTION INPUT ;
    USE SIGNAL ;
    PORT
      LAYER M4 ;
        RECT  0 40.8 0.192 40.824 ;
    END
  END qin[112]
  PIN qin[113]
    DIRECTION INPUT ;
    USE SIGNAL ;
    PORT
      LAYER M4 ;
        RECT  0 40.896 0.192 40.92 ;
    END
  END qin[113]
  PIN qin[114]
    DIRECTION INPUT ;
    USE SIGNAL ;
    PORT
      LAYER M4 ;
        RECT  0 40.992 0.192 41.016 ;
    END
  END qin[114]
  PIN qin[115]
    DIRECTION INPUT ;
    USE SIGNAL ;
    PORT
      LAYER M4 ;
        RECT  0 41.088 0.192 41.112 ;
    END
  END qin[115]
  PIN qin[116]
    DIRECTION INPUT ;
    USE SIGNAL ;
    PORT
      LAYER M4 ;
        RECT  0 41.184 0.192 41.208 ;
    END
  END qin[116]
  PIN qin[117]
    DIRECTION INPUT ;
    USE SIGNAL ;
    PORT
      LAYER M4 ;
        RECT  0 41.28 0.192 41.304 ;
    END
  END qin[117]
  PIN qin[118]
    DIRECTION INPUT ;
    USE SIGNAL ;
    PORT
      LAYER M4 ;
        RECT  0 41.376 0.192 41.4 ;
    END
  END qin[118]
  PIN qin[119]
    DIRECTION INPUT ;
    USE SIGNAL ;
    PORT
      LAYER M4 ;
        RECT  0 41.472 0.192 41.496 ;
    END
  END qin[119]
  PIN qin[11]
    DIRECTION INPUT ;
    USE SIGNAL ;
    PORT
      LAYER M4 ;
        RECT  0 31.104 0.192 31.128 ;
    END
  END qin[11]
  PIN qin[120]
    DIRECTION INPUT ;
    USE SIGNAL ;
    PORT
      LAYER M4 ;
        RECT  0 41.568 0.192 41.592 ;
    END
  END qin[120]
  PIN qin[121]
    DIRECTION INPUT ;
    USE SIGNAL ;
    PORT
      LAYER M4 ;
        RECT  0 41.664 0.192 41.688 ;
    END
  END qin[121]
  PIN qin[122]
    DIRECTION INPUT ;
    USE SIGNAL ;
    PORT
      LAYER M4 ;
        RECT  0 41.76 0.192 41.784 ;
    END
  END qin[122]
  PIN qin[123]
    DIRECTION INPUT ;
    USE SIGNAL ;
    PORT
      LAYER M4 ;
        RECT  0 41.856 0.192 41.88 ;
    END
  END qin[123]
  PIN qin[124]
    DIRECTION INPUT ;
    USE SIGNAL ;
    PORT
      LAYER M4 ;
        RECT  0 41.952 0.192 41.976 ;
    END
  END qin[124]
  PIN qin[125]
    DIRECTION INPUT ;
    USE SIGNAL ;
    PORT
      LAYER M4 ;
        RECT  0 42.048 0.192 42.072 ;
    END
  END qin[125]
  PIN qin[126]
    DIRECTION INPUT ;
    USE SIGNAL ;
    PORT
      LAYER M4 ;
        RECT  0 42.144 0.192 42.168 ;
    END
  END qin[126]
  PIN qin[127]
    DIRECTION INPUT ;
    USE SIGNAL ;
    PORT
      LAYER M4 ;
        RECT  0 42.24 0.192 42.264 ;
    END
  END qin[127]
  PIN qin[128]
    DIRECTION INPUT ;
    USE SIGNAL ;
    PORT
      LAYER M4 ;
        RECT  0 42.336 0.192 42.36 ;
    END
  END qin[128]
  PIN qin[129]
    DIRECTION INPUT ;
    USE SIGNAL ;
    PORT
      LAYER M4 ;
        RECT  0 42.432 0.192 42.456 ;
    END
  END qin[129]
  PIN qin[12]
    DIRECTION INPUT ;
    USE SIGNAL ;
    PORT
      LAYER M4 ;
        RECT  0 31.2 0.192 31.224 ;
    END
  END qin[12]
  PIN qin[130]
    DIRECTION INPUT ;
    USE SIGNAL ;
    PORT
      LAYER M4 ;
        RECT  0 42.528 0.192 42.552 ;
    END
  END qin[130]
  PIN qin[131]
    DIRECTION INPUT ;
    USE SIGNAL ;
    PORT
      LAYER M4 ;
        RECT  0 42.624 0.192 42.648 ;
    END
  END qin[131]
  PIN qin[132]
    DIRECTION INPUT ;
    USE SIGNAL ;
    PORT
      LAYER M4 ;
        RECT  0 42.72 0.192 42.744 ;
    END
  END qin[132]
  PIN qin[133]
    DIRECTION INPUT ;
    USE SIGNAL ;
    PORT
      LAYER M4 ;
        RECT  0 42.816 0.192 42.84 ;
    END
  END qin[133]
  PIN qin[134]
    DIRECTION INPUT ;
    USE SIGNAL ;
    PORT
      LAYER M4 ;
        RECT  0 42.912 0.192 42.936 ;
    END
  END qin[134]
  PIN qin[135]
    DIRECTION INPUT ;
    USE SIGNAL ;
    PORT
      LAYER M4 ;
        RECT  0 43.008 0.192 43.032 ;
    END
  END qin[135]
  PIN qin[136]
    DIRECTION INPUT ;
    USE SIGNAL ;
    PORT
      LAYER M4 ;
        RECT  0 43.104 0.192 43.128 ;
    END
  END qin[136]
  PIN qin[137]
    DIRECTION INPUT ;
    USE SIGNAL ;
    PORT
      LAYER M4 ;
        RECT  0 43.2 0.192 43.224 ;
    END
  END qin[137]
  PIN qin[13]
    DIRECTION INPUT ;
    USE SIGNAL ;
    PORT
      LAYER M4 ;
        RECT  0 31.296 0.192 31.32 ;
    END
  END qin[13]
  PIN qin[14]
    DIRECTION INPUT ;
    USE SIGNAL ;
    PORT
      LAYER M4 ;
        RECT  0 31.392 0.192 31.416 ;
    END
  END qin[14]
  PIN qin[15]
    DIRECTION INPUT ;
    USE SIGNAL ;
    PORT
      LAYER M4 ;
        RECT  0 31.488 0.192 31.512 ;
    END
  END qin[15]
  PIN qin[16]
    DIRECTION INPUT ;
    USE SIGNAL ;
    PORT
      LAYER M4 ;
        RECT  0 31.584 0.192 31.608 ;
    END
  END qin[16]
  PIN qin[17]
    DIRECTION INPUT ;
    USE SIGNAL ;
    PORT
      LAYER M4 ;
        RECT  0 31.68 0.192 31.704 ;
    END
  END qin[17]
  PIN qin[18]
    DIRECTION INPUT ;
    USE SIGNAL ;
    PORT
      LAYER M4 ;
        RECT  0 31.776 0.192 31.8 ;
    END
  END qin[18]
  PIN qin[19]
    DIRECTION INPUT ;
    USE SIGNAL ;
    PORT
      LAYER M4 ;
        RECT  0 31.872 0.192 31.896 ;
    END
  END qin[19]
  PIN qin[1]
    DIRECTION INPUT ;
    USE SIGNAL ;
    PORT
      LAYER M4 ;
        RECT  0 30.144 0.192 30.168 ;
    END
  END qin[1]
  PIN qin[20]
    DIRECTION INPUT ;
    USE SIGNAL ;
    PORT
      LAYER M4 ;
        RECT  0 31.968 0.192 31.992 ;
    END
  END qin[20]
  PIN qin[21]
    DIRECTION INPUT ;
    USE SIGNAL ;
    PORT
      LAYER M4 ;
        RECT  0 32.064 0.192 32.088 ;
    END
  END qin[21]
  PIN qin[22]
    DIRECTION INPUT ;
    USE SIGNAL ;
    PORT
      LAYER M4 ;
        RECT  0 32.16 0.192 32.184 ;
    END
  END qin[22]
  PIN qin[23]
    DIRECTION INPUT ;
    USE SIGNAL ;
    PORT
      LAYER M4 ;
        RECT  0 32.256 0.192 32.28 ;
    END
  END qin[23]
  PIN qin[24]
    DIRECTION INPUT ;
    USE SIGNAL ;
    PORT
      LAYER M4 ;
        RECT  0 32.352 0.192 32.376 ;
    END
  END qin[24]
  PIN qin[25]
    DIRECTION INPUT ;
    USE SIGNAL ;
    PORT
      LAYER M4 ;
        RECT  0 32.448 0.192 32.472 ;
    END
  END qin[25]
  PIN qin[26]
    DIRECTION INPUT ;
    USE SIGNAL ;
    PORT
      LAYER M4 ;
        RECT  0 32.544 0.192 32.568 ;
    END
  END qin[26]
  PIN qin[27]
    DIRECTION INPUT ;
    USE SIGNAL ;
    PORT
      LAYER M4 ;
        RECT  0 32.64 0.192 32.664 ;
    END
  END qin[27]
  PIN qin[28]
    DIRECTION INPUT ;
    USE SIGNAL ;
    PORT
      LAYER M4 ;
        RECT  0 32.736 0.192 32.76 ;
    END
  END qin[28]
  PIN qin[29]
    DIRECTION INPUT ;
    USE SIGNAL ;
    PORT
      LAYER M4 ;
        RECT  0 32.832 0.192 32.856 ;
    END
  END qin[29]
  PIN qin[2]
    DIRECTION INPUT ;
    USE SIGNAL ;
    PORT
      LAYER M4 ;
        RECT  0 30.24 0.192 30.264 ;
    END
  END qin[2]
  PIN qin[30]
    DIRECTION INPUT ;
    USE SIGNAL ;
    PORT
      LAYER M4 ;
        RECT  0 32.928 0.192 32.952 ;
    END
  END qin[30]
  PIN qin[31]
    DIRECTION INPUT ;
    USE SIGNAL ;
    PORT
      LAYER M4 ;
        RECT  0 33.024 0.192 33.048 ;
    END
  END qin[31]
  PIN qin[32]
    DIRECTION INPUT ;
    USE SIGNAL ;
    PORT
      LAYER M4 ;
        RECT  0 33.12 0.192 33.144 ;
    END
  END qin[32]
  PIN qin[33]
    DIRECTION INPUT ;
    USE SIGNAL ;
    PORT
      LAYER M4 ;
        RECT  0 33.216 0.192 33.24 ;
    END
  END qin[33]
  PIN qin[34]
    DIRECTION INPUT ;
    USE SIGNAL ;
    PORT
      LAYER M4 ;
        RECT  0 33.312 0.192 33.336 ;
    END
  END qin[34]
  PIN qin[35]
    DIRECTION INPUT ;
    USE SIGNAL ;
    PORT
      LAYER M4 ;
        RECT  0 33.408 0.192 33.432 ;
    END
  END qin[35]
  PIN qin[36]
    DIRECTION INPUT ;
    USE SIGNAL ;
    PORT
      LAYER M4 ;
        RECT  0 33.504 0.192 33.528 ;
    END
  END qin[36]
  PIN qin[37]
    DIRECTION INPUT ;
    USE SIGNAL ;
    PORT
      LAYER M4 ;
        RECT  0 33.6 0.192 33.624 ;
    END
  END qin[37]
  PIN qin[38]
    DIRECTION INPUT ;
    USE SIGNAL ;
    PORT
      LAYER M4 ;
        RECT  0 33.696 0.192 33.72 ;
    END
  END qin[38]
  PIN qin[39]
    DIRECTION INPUT ;
    USE SIGNAL ;
    PORT
      LAYER M4 ;
        RECT  0 33.792 0.192 33.816 ;
    END
  END qin[39]
  PIN qin[3]
    DIRECTION INPUT ;
    USE SIGNAL ;
    PORT
      LAYER M4 ;
        RECT  0 30.336 0.192 30.36 ;
    END
  END qin[3]
  PIN qin[40]
    DIRECTION INPUT ;
    USE SIGNAL ;
    PORT
      LAYER M4 ;
        RECT  0 33.888 0.192 33.912 ;
    END
  END qin[40]
  PIN qin[41]
    DIRECTION INPUT ;
    USE SIGNAL ;
    PORT
      LAYER M4 ;
        RECT  0 33.984 0.192 34.008 ;
    END
  END qin[41]
  PIN qin[42]
    DIRECTION INPUT ;
    USE SIGNAL ;
    PORT
      LAYER M4 ;
        RECT  0 34.08 0.192 34.104 ;
    END
  END qin[42]
  PIN qin[43]
    DIRECTION INPUT ;
    USE SIGNAL ;
    PORT
      LAYER M4 ;
        RECT  0 34.176 0.192 34.2 ;
    END
  END qin[43]
  PIN qin[44]
    DIRECTION INPUT ;
    USE SIGNAL ;
    PORT
      LAYER M4 ;
        RECT  0 34.272 0.192 34.296 ;
    END
  END qin[44]
  PIN qin[45]
    DIRECTION INPUT ;
    USE SIGNAL ;
    PORT
      LAYER M4 ;
        RECT  0 34.368 0.192 34.392 ;
    END
  END qin[45]
  PIN qin[46]
    DIRECTION INPUT ;
    USE SIGNAL ;
    PORT
      LAYER M4 ;
        RECT  0 34.464 0.192 34.488 ;
    END
  END qin[46]
  PIN qin[47]
    DIRECTION INPUT ;
    USE SIGNAL ;
    PORT
      LAYER M4 ;
        RECT  0 34.56 0.192 34.584 ;
    END
  END qin[47]
  PIN qin[48]
    DIRECTION INPUT ;
    USE SIGNAL ;
    PORT
      LAYER M4 ;
        RECT  0 34.656 0.192 34.68 ;
    END
  END qin[48]
  PIN qin[49]
    DIRECTION INPUT ;
    USE SIGNAL ;
    PORT
      LAYER M4 ;
        RECT  0 34.752 0.192 34.776 ;
    END
  END qin[49]
  PIN qin[4]
    DIRECTION INPUT ;
    USE SIGNAL ;
    PORT
      LAYER M4 ;
        RECT  0 30.432 0.192 30.456 ;
    END
  END qin[4]
  PIN qin[50]
    DIRECTION INPUT ;
    USE SIGNAL ;
    PORT
      LAYER M4 ;
        RECT  0 34.848 0.192 34.872 ;
    END
  END qin[50]
  PIN qin[51]
    DIRECTION INPUT ;
    USE SIGNAL ;
    PORT
      LAYER M4 ;
        RECT  0 34.944 0.192 34.968 ;
    END
  END qin[51]
  PIN qin[52]
    DIRECTION INPUT ;
    USE SIGNAL ;
    PORT
      LAYER M4 ;
        RECT  0 35.04 0.192 35.064 ;
    END
  END qin[52]
  PIN qin[53]
    DIRECTION INPUT ;
    USE SIGNAL ;
    PORT
      LAYER M4 ;
        RECT  0 35.136 0.192 35.16 ;
    END
  END qin[53]
  PIN qin[54]
    DIRECTION INPUT ;
    USE SIGNAL ;
    PORT
      LAYER M4 ;
        RECT  0 35.232 0.192 35.256 ;
    END
  END qin[54]
  PIN qin[55]
    DIRECTION INPUT ;
    USE SIGNAL ;
    PORT
      LAYER M4 ;
        RECT  0 35.328 0.192 35.352 ;
    END
  END qin[55]
  PIN qin[56]
    DIRECTION INPUT ;
    USE SIGNAL ;
    PORT
      LAYER M4 ;
        RECT  0 35.424 0.192 35.448 ;
    END
  END qin[56]
  PIN qin[57]
    DIRECTION INPUT ;
    USE SIGNAL ;
    PORT
      LAYER M4 ;
        RECT  0 35.52 0.192 35.544 ;
    END
  END qin[57]
  PIN qin[58]
    DIRECTION INPUT ;
    USE SIGNAL ;
    PORT
      LAYER M4 ;
        RECT  0 35.616 0.192 35.64 ;
    END
  END qin[58]
  PIN qin[59]
    DIRECTION INPUT ;
    USE SIGNAL ;
    PORT
      LAYER M4 ;
        RECT  0 35.712 0.192 35.736 ;
    END
  END qin[59]
  PIN qin[5]
    DIRECTION INPUT ;
    USE SIGNAL ;
    PORT
      LAYER M4 ;
        RECT  0 30.528 0.192 30.552 ;
    END
  END qin[5]
  PIN qin[60]
    DIRECTION INPUT ;
    USE SIGNAL ;
    PORT
      LAYER M4 ;
        RECT  0 35.808 0.192 35.832 ;
    END
  END qin[60]
  PIN qin[61]
    DIRECTION INPUT ;
    USE SIGNAL ;
    PORT
      LAYER M4 ;
        RECT  0 35.904 0.192 35.928 ;
    END
  END qin[61]
  PIN qin[62]
    DIRECTION INPUT ;
    USE SIGNAL ;
    PORT
      LAYER M4 ;
        RECT  0 36 0.192 36.024 ;
    END
  END qin[62]
  PIN qin[63]
    DIRECTION INPUT ;
    USE SIGNAL ;
    PORT
      LAYER M4 ;
        RECT  0 36.096 0.192 36.12 ;
    END
  END qin[63]
  PIN qin[64]
    DIRECTION INPUT ;
    USE SIGNAL ;
    PORT
      LAYER M4 ;
        RECT  0 36.192 0.192 36.216 ;
    END
  END qin[64]
  PIN qin[65]
    DIRECTION INPUT ;
    USE SIGNAL ;
    PORT
      LAYER M4 ;
        RECT  0 36.288 0.192 36.312 ;
    END
  END qin[65]
  PIN qin[66]
    DIRECTION INPUT ;
    USE SIGNAL ;
    PORT
      LAYER M4 ;
        RECT  0 36.384 0.192 36.408 ;
    END
  END qin[66]
  PIN qin[67]
    DIRECTION INPUT ;
    USE SIGNAL ;
    PORT
      LAYER M4 ;
        RECT  0 36.48 0.192 36.504 ;
    END
  END qin[67]
  PIN qin[68]
    DIRECTION INPUT ;
    USE SIGNAL ;
    PORT
      LAYER M4 ;
        RECT  0 36.576 0.192 36.6 ;
    END
  END qin[68]
  PIN qin[69]
    DIRECTION INPUT ;
    USE SIGNAL ;
    PORT
      LAYER M4 ;
        RECT  0 36.672 0.192 36.696 ;
    END
  END qin[69]
  PIN qin[6]
    DIRECTION INPUT ;
    USE SIGNAL ;
    PORT
      LAYER M4 ;
        RECT  0 30.624 0.192 30.648 ;
    END
  END qin[6]
  PIN qin[70]
    DIRECTION INPUT ;
    USE SIGNAL ;
    PORT
      LAYER M4 ;
        RECT  0 36.768 0.192 36.792 ;
    END
  END qin[70]
  PIN qin[71]
    DIRECTION INPUT ;
    USE SIGNAL ;
    PORT
      LAYER M4 ;
        RECT  0 36.864 0.192 36.888 ;
    END
  END qin[71]
  PIN qin[72]
    DIRECTION INPUT ;
    USE SIGNAL ;
    PORT
      LAYER M4 ;
        RECT  0 36.96 0.192 36.984 ;
    END
  END qin[72]
  PIN qin[73]
    DIRECTION INPUT ;
    USE SIGNAL ;
    PORT
      LAYER M4 ;
        RECT  0 37.056 0.192 37.08 ;
    END
  END qin[73]
  PIN qin[74]
    DIRECTION INPUT ;
    USE SIGNAL ;
    PORT
      LAYER M4 ;
        RECT  0 37.152 0.192 37.176 ;
    END
  END qin[74]
  PIN qin[75]
    DIRECTION INPUT ;
    USE SIGNAL ;
    PORT
      LAYER M4 ;
        RECT  0 37.248 0.192 37.272 ;
    END
  END qin[75]
  PIN qin[76]
    DIRECTION INPUT ;
    USE SIGNAL ;
    PORT
      LAYER M4 ;
        RECT  0 37.344 0.192 37.368 ;
    END
  END qin[76]
  PIN qin[77]
    DIRECTION INPUT ;
    USE SIGNAL ;
    PORT
      LAYER M4 ;
        RECT  0 37.44 0.192 37.464 ;
    END
  END qin[77]
  PIN qin[78]
    DIRECTION INPUT ;
    USE SIGNAL ;
    PORT
      LAYER M4 ;
        RECT  0 37.536 0.192 37.56 ;
    END
  END qin[78]
  PIN qin[79]
    DIRECTION INPUT ;
    USE SIGNAL ;
    PORT
      LAYER M4 ;
        RECT  0 37.632 0.192 37.656 ;
    END
  END qin[79]
  PIN qin[7]
    DIRECTION INPUT ;
    USE SIGNAL ;
    PORT
      LAYER M4 ;
        RECT  0 30.72 0.192 30.744 ;
    END
  END qin[7]
  PIN qin[80]
    DIRECTION INPUT ;
    USE SIGNAL ;
    PORT
      LAYER M4 ;
        RECT  0 37.728 0.192 37.752 ;
    END
  END qin[80]
  PIN qin[81]
    DIRECTION INPUT ;
    USE SIGNAL ;
    PORT
      LAYER M4 ;
        RECT  0 37.824 0.192 37.848 ;
    END
  END qin[81]
  PIN qin[82]
    DIRECTION INPUT ;
    USE SIGNAL ;
    PORT
      LAYER M4 ;
        RECT  0 37.92 0.192 37.944 ;
    END
  END qin[82]
  PIN qin[83]
    DIRECTION INPUT ;
    USE SIGNAL ;
    PORT
      LAYER M4 ;
        RECT  0 38.016 0.192 38.04 ;
    END
  END qin[83]
  PIN qin[84]
    DIRECTION INPUT ;
    USE SIGNAL ;
    PORT
      LAYER M4 ;
        RECT  0 38.112 0.192 38.136 ;
    END
  END qin[84]
  PIN qin[85]
    DIRECTION INPUT ;
    USE SIGNAL ;
    PORT
      LAYER M4 ;
        RECT  0 38.208 0.192 38.232 ;
    END
  END qin[85]
  PIN qin[86]
    DIRECTION INPUT ;
    USE SIGNAL ;
    PORT
      LAYER M4 ;
        RECT  0 38.304 0.192 38.328 ;
    END
  END qin[86]
  PIN qin[87]
    DIRECTION INPUT ;
    USE SIGNAL ;
    PORT
      LAYER M4 ;
        RECT  0 38.4 0.192 38.424 ;
    END
  END qin[87]
  PIN qin[88]
    DIRECTION INPUT ;
    USE SIGNAL ;
    PORT
      LAYER M4 ;
        RECT  0 38.496 0.192 38.52 ;
    END
  END qin[88]
  PIN qin[89]
    DIRECTION INPUT ;
    USE SIGNAL ;
    PORT
      LAYER M4 ;
        RECT  0 38.592 0.192 38.616 ;
    END
  END qin[89]
  PIN qin[8]
    DIRECTION INPUT ;
    USE SIGNAL ;
    PORT
      LAYER M4 ;
        RECT  0 30.816 0.192 30.84 ;
    END
  END qin[8]
  PIN qin[90]
    DIRECTION INPUT ;
    USE SIGNAL ;
    PORT
      LAYER M4 ;
        RECT  0 38.688 0.192 38.712 ;
    END
  END qin[90]
  PIN qin[91]
    DIRECTION INPUT ;
    USE SIGNAL ;
    PORT
      LAYER M4 ;
        RECT  0 38.784 0.192 38.808 ;
    END
  END qin[91]
  PIN qin[92]
    DIRECTION INPUT ;
    USE SIGNAL ;
    PORT
      LAYER M4 ;
        RECT  0 38.88 0.192 38.904 ;
    END
  END qin[92]
  PIN qin[93]
    DIRECTION INPUT ;
    USE SIGNAL ;
    PORT
      LAYER M4 ;
        RECT  0 38.976 0.192 39 ;
    END
  END qin[93]
  PIN qin[94]
    DIRECTION INPUT ;
    USE SIGNAL ;
    PORT
      LAYER M4 ;
        RECT  0 39.072 0.192 39.096 ;
    END
  END qin[94]
  PIN qin[95]
    DIRECTION INPUT ;
    USE SIGNAL ;
    PORT
      LAYER M4 ;
        RECT  0 39.168 0.192 39.192 ;
    END
  END qin[95]
  PIN qin[96]
    DIRECTION INPUT ;
    USE SIGNAL ;
    PORT
      LAYER M4 ;
        RECT  0 39.264 0.192 39.288 ;
    END
  END qin[96]
  PIN qin[97]
    DIRECTION INPUT ;
    USE SIGNAL ;
    PORT
      LAYER M4 ;
        RECT  0 39.36 0.192 39.384 ;
    END
  END qin[97]
  PIN qin[98]
    DIRECTION INPUT ;
    USE SIGNAL ;
    PORT
      LAYER M4 ;
        RECT  0 39.456 0.192 39.48 ;
    END
  END qin[98]
  PIN qin[99]
    DIRECTION INPUT ;
    USE SIGNAL ;
    PORT
      LAYER M4 ;
        RECT  0 39.552 0.192 39.576 ;
    END
  END qin[99]
  PIN qin[9]
    DIRECTION INPUT ;
    USE SIGNAL ;
    PORT
      LAYER M4 ;
        RECT  0 30.912 0.192 30.936 ;
    END
  END qin[9]
  PIN qout[0]
    DIRECTION OUTPUT ;
    USE SIGNAL ;
    PORT
      LAYER M4 ;
        RECT  319.488 30.048 319.68 30.072 ;
    END
  END qout[0]
  PIN qout[100]
    DIRECTION OUTPUT ;
    USE SIGNAL ;
    PORT
      LAYER M4 ;
        RECT  319.488 39.648 319.68 39.672 ;
    END
  END qout[100]
  PIN qout[101]
    DIRECTION OUTPUT ;
    USE SIGNAL ;
    PORT
      LAYER M4 ;
        RECT  319.488 39.744 319.68 39.768 ;
    END
  END qout[101]
  PIN qout[102]
    DIRECTION OUTPUT ;
    USE SIGNAL ;
    PORT
      LAYER M4 ;
        RECT  319.488 39.84 319.68 39.864 ;
    END
  END qout[102]
  PIN qout[103]
    DIRECTION OUTPUT ;
    USE SIGNAL ;
    PORT
      LAYER M4 ;
        RECT  319.488 39.936 319.68 39.96 ;
    END
  END qout[103]
  PIN qout[104]
    DIRECTION OUTPUT ;
    USE SIGNAL ;
    PORT
      LAYER M4 ;
        RECT  319.488 40.032 319.68 40.056 ;
    END
  END qout[104]
  PIN qout[105]
    DIRECTION OUTPUT ;
    USE SIGNAL ;
    PORT
      LAYER M4 ;
        RECT  319.488 40.128 319.68 40.152 ;
    END
  END qout[105]
  PIN qout[106]
    DIRECTION OUTPUT ;
    USE SIGNAL ;
    PORT
      LAYER M4 ;
        RECT  319.488 40.224 319.68 40.248 ;
    END
  END qout[106]
  PIN qout[107]
    DIRECTION OUTPUT ;
    USE SIGNAL ;
    PORT
      LAYER M4 ;
        RECT  319.488 40.32 319.68 40.344 ;
    END
  END qout[107]
  PIN qout[108]
    DIRECTION OUTPUT ;
    USE SIGNAL ;
    PORT
      LAYER M4 ;
        RECT  319.488 40.416 319.68 40.44 ;
    END
  END qout[108]
  PIN qout[109]
    DIRECTION OUTPUT ;
    USE SIGNAL ;
    PORT
      LAYER M4 ;
        RECT  319.488 40.512 319.68 40.536 ;
    END
  END qout[109]
  PIN qout[10]
    DIRECTION OUTPUT ;
    USE SIGNAL ;
    PORT
      LAYER M4 ;
        RECT  319.488 31.008 319.68 31.032 ;
    END
  END qout[10]
  PIN qout[110]
    DIRECTION OUTPUT ;
    USE SIGNAL ;
    PORT
      LAYER M4 ;
        RECT  319.488 40.608 319.68 40.632 ;
    END
  END qout[110]
  PIN qout[111]
    DIRECTION OUTPUT ;
    USE SIGNAL ;
    PORT
      LAYER M4 ;
        RECT  319.488 40.704 319.68 40.728 ;
    END
  END qout[111]
  PIN qout[112]
    DIRECTION OUTPUT ;
    USE SIGNAL ;
    PORT
      LAYER M4 ;
        RECT  319.488 40.8 319.68 40.824 ;
    END
  END qout[112]
  PIN qout[113]
    DIRECTION OUTPUT ;
    USE SIGNAL ;
    PORT
      LAYER M4 ;
        RECT  319.488 40.896 319.68 40.92 ;
    END
  END qout[113]
  PIN qout[114]
    DIRECTION OUTPUT ;
    USE SIGNAL ;
    PORT
      LAYER M4 ;
        RECT  319.488 40.992 319.68 41.016 ;
    END
  END qout[114]
  PIN qout[115]
    DIRECTION OUTPUT ;
    USE SIGNAL ;
    PORT
      LAYER M4 ;
        RECT  319.488 41.088 319.68 41.112 ;
    END
  END qout[115]
  PIN qout[116]
    DIRECTION OUTPUT ;
    USE SIGNAL ;
    PORT
      LAYER M4 ;
        RECT  319.488 41.184 319.68 41.208 ;
    END
  END qout[116]
  PIN qout[117]
    DIRECTION OUTPUT ;
    USE SIGNAL ;
    PORT
      LAYER M4 ;
        RECT  319.488 41.28 319.68 41.304 ;
    END
  END qout[117]
  PIN qout[118]
    DIRECTION OUTPUT ;
    USE SIGNAL ;
    PORT
      LAYER M4 ;
        RECT  319.488 41.376 319.68 41.4 ;
    END
  END qout[118]
  PIN qout[119]
    DIRECTION OUTPUT ;
    USE SIGNAL ;
    PORT
      LAYER M4 ;
        RECT  319.488 41.472 319.68 41.496 ;
    END
  END qout[119]
  PIN qout[11]
    DIRECTION OUTPUT ;
    USE SIGNAL ;
    PORT
      LAYER M4 ;
        RECT  319.488 31.104 319.68 31.128 ;
    END
  END qout[11]
  PIN qout[120]
    DIRECTION OUTPUT ;
    USE SIGNAL ;
    PORT
      LAYER M4 ;
        RECT  319.488 41.568 319.68 41.592 ;
    END
  END qout[120]
  PIN qout[121]
    DIRECTION OUTPUT ;
    USE SIGNAL ;
    PORT
      LAYER M4 ;
        RECT  319.488 41.664 319.68 41.688 ;
    END
  END qout[121]
  PIN qout[122]
    DIRECTION OUTPUT ;
    USE SIGNAL ;
    PORT
      LAYER M4 ;
        RECT  319.488 41.76 319.68 41.784 ;
    END
  END qout[122]
  PIN qout[123]
    DIRECTION OUTPUT ;
    USE SIGNAL ;
    PORT
      LAYER M4 ;
        RECT  319.488 41.856 319.68 41.88 ;
    END
  END qout[123]
  PIN qout[124]
    DIRECTION OUTPUT ;
    USE SIGNAL ;
    PORT
      LAYER M4 ;
        RECT  319.488 41.952 319.68 41.976 ;
    END
  END qout[124]
  PIN qout[125]
    DIRECTION OUTPUT ;
    USE SIGNAL ;
    PORT
      LAYER M4 ;
        RECT  319.488 42.048 319.68 42.072 ;
    END
  END qout[125]
  PIN qout[126]
    DIRECTION OUTPUT ;
    USE SIGNAL ;
    PORT
      LAYER M4 ;
        RECT  319.488 42.144 319.68 42.168 ;
    END
  END qout[126]
  PIN qout[127]
    DIRECTION OUTPUT ;
    USE SIGNAL ;
    PORT
      LAYER M4 ;
        RECT  319.488 42.24 319.68 42.264 ;
    END
  END qout[127]
  PIN qout[128]
    DIRECTION OUTPUT ;
    USE SIGNAL ;
    PORT
      LAYER M4 ;
        RECT  319.488 42.336 319.68 42.36 ;
    END
  END qout[128]
  PIN qout[129]
    DIRECTION OUTPUT ;
    USE SIGNAL ;
    PORT
      LAYER M4 ;
        RECT  319.488 42.432 319.68 42.456 ;
    END
  END qout[129]
  PIN qout[12]
    DIRECTION OUTPUT ;
    USE SIGNAL ;
    PORT
      LAYER M4 ;
        RECT  319.488 31.2 319.68 31.224 ;
    END
  END qout[12]
  PIN qout[130]
    DIRECTION OUTPUT ;
    USE SIGNAL ;
    PORT
      LAYER M4 ;
        RECT  319.488 42.528 319.68 42.552 ;
    END
  END qout[130]
  PIN qout[131]
    DIRECTION OUTPUT ;
    USE SIGNAL ;
    PORT
      LAYER M4 ;
        RECT  319.488 42.624 319.68 42.648 ;
    END
  END qout[131]
  PIN qout[132]
    DIRECTION OUTPUT ;
    USE SIGNAL ;
    PORT
      LAYER M4 ;
        RECT  319.488 42.72 319.68 42.744 ;
    END
  END qout[132]
  PIN qout[133]
    DIRECTION OUTPUT ;
    USE SIGNAL ;
    PORT
      LAYER M4 ;
        RECT  319.488 42.816 319.68 42.84 ;
    END
  END qout[133]
  PIN qout[134]
    DIRECTION OUTPUT ;
    USE SIGNAL ;
    PORT
      LAYER M4 ;
        RECT  319.488 42.912 319.68 42.936 ;
    END
  END qout[134]
  PIN qout[135]
    DIRECTION OUTPUT ;
    USE SIGNAL ;
    PORT
      LAYER M4 ;
        RECT  319.488 43.008 319.68 43.032 ;
    END
  END qout[135]
  PIN qout[136]
    DIRECTION OUTPUT ;
    USE SIGNAL ;
    PORT
      LAYER M4 ;
        RECT  319.488 43.104 319.68 43.128 ;
    END
  END qout[136]
  PIN qout[137]
    DIRECTION OUTPUT ;
    USE SIGNAL ;
    PORT
      LAYER M4 ;
        RECT  319.488 43.2 319.68 43.224 ;
    END
  END qout[137]
  PIN qout[138]
    DIRECTION OUTPUT ;
    USE SIGNAL ;
    PORT
      LAYER M4 ;
        RECT  319.488 43.296 319.68 43.32 ;
    END
  END qout[138]
  PIN qout[139]
    DIRECTION OUTPUT ;
    USE SIGNAL ;
    PORT
      LAYER M4 ;
        RECT  319.488 43.392 319.68 43.416 ;
    END
  END qout[139]
  PIN qout[13]
    DIRECTION OUTPUT ;
    USE SIGNAL ;
    PORT
      LAYER M4 ;
        RECT  319.488 31.296 319.68 31.32 ;
    END
  END qout[13]
  PIN qout[140]
    DIRECTION OUTPUT ;
    USE SIGNAL ;
    PORT
      LAYER M4 ;
        RECT  319.488 43.488 319.68 43.512 ;
    END
  END qout[140]
  PIN qout[141]
    DIRECTION OUTPUT ;
    USE SIGNAL ;
    PORT
      LAYER M4 ;
        RECT  319.488 43.584 319.68 43.608 ;
    END
  END qout[141]
  PIN qout[142]
    DIRECTION OUTPUT ;
    USE SIGNAL ;
    PORT
      LAYER M4 ;
        RECT  319.488 43.68 319.68 43.704 ;
    END
  END qout[142]
  PIN qout[143]
    DIRECTION OUTPUT ;
    USE SIGNAL ;
    PORT
      LAYER M4 ;
        RECT  319.488 43.776 319.68 43.8 ;
    END
  END qout[143]
  PIN qout[144]
    DIRECTION OUTPUT ;
    USE SIGNAL ;
    PORT
      LAYER M4 ;
        RECT  319.488 43.872 319.68 43.896 ;
    END
  END qout[144]
  PIN qout[145]
    DIRECTION OUTPUT ;
    USE SIGNAL ;
    PORT
      LAYER M4 ;
        RECT  319.488 43.968 319.68 43.992 ;
    END
  END qout[145]
  PIN qout[146]
    DIRECTION OUTPUT ;
    USE SIGNAL ;
    PORT
      LAYER M4 ;
        RECT  319.488 44.064 319.68 44.088 ;
    END
  END qout[146]
  PIN qout[147]
    DIRECTION OUTPUT ;
    USE SIGNAL ;
    PORT
      LAYER M4 ;
        RECT  319.488 44.16 319.68 44.184 ;
    END
  END qout[147]
  PIN qout[148]
    DIRECTION OUTPUT ;
    USE SIGNAL ;
    PORT
      LAYER M4 ;
        RECT  319.488 44.256 319.68 44.28 ;
    END
  END qout[148]
  PIN qout[149]
    DIRECTION OUTPUT ;
    USE SIGNAL ;
    PORT
      LAYER M4 ;
        RECT  319.488 44.352 319.68 44.376 ;
    END
  END qout[149]
  PIN qout[14]
    DIRECTION OUTPUT ;
    USE SIGNAL ;
    PORT
      LAYER M4 ;
        RECT  319.488 31.392 319.68 31.416 ;
    END
  END qout[14]
  PIN qout[150]
    DIRECTION OUTPUT ;
    USE SIGNAL ;
    PORT
      LAYER M4 ;
        RECT  319.488 44.448 319.68 44.472 ;
    END
  END qout[150]
  PIN qout[151]
    DIRECTION OUTPUT ;
    USE SIGNAL ;
    PORT
      LAYER M4 ;
        RECT  319.488 44.544 319.68 44.568 ;
    END
  END qout[151]
  PIN qout[152]
    DIRECTION OUTPUT ;
    USE SIGNAL ;
    PORT
      LAYER M4 ;
        RECT  319.488 44.64 319.68 44.664 ;
    END
  END qout[152]
  PIN qout[153]
    DIRECTION OUTPUT ;
    USE SIGNAL ;
    PORT
      LAYER M4 ;
        RECT  319.488 44.736 319.68 44.76 ;
    END
  END qout[153]
  PIN qout[154]
    DIRECTION OUTPUT ;
    USE SIGNAL ;
    PORT
      LAYER M4 ;
        RECT  319.488 44.832 319.68 44.856 ;
    END
  END qout[154]
  PIN qout[155]
    DIRECTION OUTPUT ;
    USE SIGNAL ;
    PORT
      LAYER M4 ;
        RECT  319.488 44.928 319.68 44.952 ;
    END
  END qout[155]
  PIN qout[156]
    DIRECTION OUTPUT ;
    USE SIGNAL ;
    PORT
      LAYER M4 ;
        RECT  319.488 45.024 319.68 45.048 ;
    END
  END qout[156]
  PIN qout[157]
    DIRECTION OUTPUT ;
    USE SIGNAL ;
    PORT
      LAYER M4 ;
        RECT  319.488 45.12 319.68 45.144 ;
    END
  END qout[157]
  PIN qout[158]
    DIRECTION OUTPUT ;
    USE SIGNAL ;
    PORT
      LAYER M4 ;
        RECT  319.488 45.216 319.68 45.24 ;
    END
  END qout[158]
  PIN qout[159]
    DIRECTION OUTPUT ;
    USE SIGNAL ;
    PORT
      LAYER M4 ;
        RECT  319.488 45.312 319.68 45.336 ;
    END
  END qout[159]
  PIN qout[15]
    DIRECTION OUTPUT ;
    USE SIGNAL ;
    PORT
      LAYER M4 ;
        RECT  319.488 31.488 319.68 31.512 ;
    END
  END qout[15]
  PIN qout[160]
    DIRECTION OUTPUT ;
    USE SIGNAL ;
    PORT
      LAYER M4 ;
        RECT  319.488 45.408 319.68 45.432 ;
    END
  END qout[160]
  PIN qout[161]
    DIRECTION OUTPUT ;
    USE SIGNAL ;
    PORT
      LAYER M4 ;
        RECT  319.488 45.504 319.68 45.528 ;
    END
  END qout[161]
  PIN qout[162]
    DIRECTION OUTPUT ;
    USE SIGNAL ;
    PORT
      LAYER M4 ;
        RECT  319.488 45.6 319.68 45.624 ;
    END
  END qout[162]
  PIN qout[163]
    DIRECTION OUTPUT ;
    USE SIGNAL ;
    PORT
      LAYER M4 ;
        RECT  319.488 45.696 319.68 45.72 ;
    END
  END qout[163]
  PIN qout[164]
    DIRECTION OUTPUT ;
    USE SIGNAL ;
    PORT
      LAYER M4 ;
        RECT  319.488 45.792 319.68 45.816 ;
    END
  END qout[164]
  PIN qout[165]
    DIRECTION OUTPUT ;
    USE SIGNAL ;
    PORT
      LAYER M4 ;
        RECT  319.488 45.888 319.68 45.912 ;
    END
  END qout[165]
  PIN qout[166]
    DIRECTION OUTPUT ;
    USE SIGNAL ;
    PORT
      LAYER M4 ;
        RECT  319.488 45.984 319.68 46.008 ;
    END
  END qout[166]
  PIN qout[167]
    DIRECTION OUTPUT ;
    USE SIGNAL ;
    PORT
      LAYER M4 ;
        RECT  319.488 46.08 319.68 46.104 ;
    END
  END qout[167]
  PIN qout[168]
    DIRECTION OUTPUT ;
    USE SIGNAL ;
    PORT
      LAYER M4 ;
        RECT  319.488 46.176 319.68 46.2 ;
    END
  END qout[168]
  PIN qout[169]
    DIRECTION OUTPUT ;
    USE SIGNAL ;
    PORT
      LAYER M4 ;
        RECT  319.488 46.272 319.68 46.296 ;
    END
  END qout[169]
  PIN qout[16]
    DIRECTION OUTPUT ;
    USE SIGNAL ;
    PORT
      LAYER M4 ;
        RECT  319.488 31.584 319.68 31.608 ;
    END
  END qout[16]
  PIN qout[170]
    DIRECTION OUTPUT ;
    USE SIGNAL ;
    PORT
      LAYER M4 ;
        RECT  319.488 46.368 319.68 46.392 ;
    END
  END qout[170]
  PIN qout[171]
    DIRECTION OUTPUT ;
    USE SIGNAL ;
    PORT
      LAYER M4 ;
        RECT  319.488 46.464 319.68 46.488 ;
    END
  END qout[171]
  PIN qout[172]
    DIRECTION OUTPUT ;
    USE SIGNAL ;
    PORT
      LAYER M4 ;
        RECT  319.488 46.56 319.68 46.584 ;
    END
  END qout[172]
  PIN qout[173]
    DIRECTION OUTPUT ;
    USE SIGNAL ;
    PORT
      LAYER M4 ;
        RECT  319.488 46.656 319.68 46.68 ;
    END
  END qout[173]
  PIN qout[174]
    DIRECTION OUTPUT ;
    USE SIGNAL ;
    PORT
      LAYER M4 ;
        RECT  319.488 46.752 319.68 46.776 ;
    END
  END qout[174]
  PIN qout[175]
    DIRECTION OUTPUT ;
    USE SIGNAL ;
    PORT
      LAYER M4 ;
        RECT  319.488 46.848 319.68 46.872 ;
    END
  END qout[175]
  PIN qout[176]
    DIRECTION OUTPUT ;
    USE SIGNAL ;
    PORT
      LAYER M4 ;
        RECT  319.488 46.944 319.68 46.968 ;
    END
  END qout[176]
  PIN qout[177]
    DIRECTION OUTPUT ;
    USE SIGNAL ;
    PORT
      LAYER M4 ;
        RECT  319.488 47.04 319.68 47.064 ;
    END
  END qout[177]
  PIN qout[178]
    DIRECTION OUTPUT ;
    USE SIGNAL ;
    PORT
      LAYER M4 ;
        RECT  319.488 47.136 319.68 47.16 ;
    END
  END qout[178]
  PIN qout[179]
    DIRECTION OUTPUT ;
    USE SIGNAL ;
    PORT
      LAYER M4 ;
        RECT  319.488 47.232 319.68 47.256 ;
    END
  END qout[179]
  PIN qout[17]
    DIRECTION OUTPUT ;
    USE SIGNAL ;
    PORT
      LAYER M4 ;
        RECT  319.488 31.68 319.68 31.704 ;
    END
  END qout[17]
  PIN qout[180]
    DIRECTION OUTPUT ;
    USE SIGNAL ;
    PORT
      LAYER M4 ;
        RECT  319.488 47.328 319.68 47.352 ;
    END
  END qout[180]
  PIN qout[181]
    DIRECTION OUTPUT ;
    USE SIGNAL ;
    PORT
      LAYER M4 ;
        RECT  319.488 47.424 319.68 47.448 ;
    END
  END qout[181]
  PIN qout[182]
    DIRECTION OUTPUT ;
    USE SIGNAL ;
    PORT
      LAYER M4 ;
        RECT  319.488 47.52 319.68 47.544 ;
    END
  END qout[182]
  PIN qout[183]
    DIRECTION OUTPUT ;
    USE SIGNAL ;
    PORT
      LAYER M4 ;
        RECT  319.488 47.616 319.68 47.64 ;
    END
  END qout[183]
  PIN qout[18]
    DIRECTION OUTPUT ;
    USE SIGNAL ;
    PORT
      LAYER M4 ;
        RECT  319.488 31.776 319.68 31.8 ;
    END
  END qout[18]
  PIN qout[19]
    DIRECTION OUTPUT ;
    USE SIGNAL ;
    PORT
      LAYER M4 ;
        RECT  319.488 31.872 319.68 31.896 ;
    END
  END qout[19]
  PIN qout[1]
    DIRECTION OUTPUT ;
    USE SIGNAL ;
    PORT
      LAYER M4 ;
        RECT  319.488 30.144 319.68 30.168 ;
    END
  END qout[1]
  PIN qout[20]
    DIRECTION OUTPUT ;
    USE SIGNAL ;
    PORT
      LAYER M4 ;
        RECT  319.488 31.968 319.68 31.992 ;
    END
  END qout[20]
  PIN qout[21]
    DIRECTION OUTPUT ;
    USE SIGNAL ;
    PORT
      LAYER M4 ;
        RECT  319.488 32.064 319.68 32.088 ;
    END
  END qout[21]
  PIN qout[22]
    DIRECTION OUTPUT ;
    USE SIGNAL ;
    PORT
      LAYER M4 ;
        RECT  319.488 32.16 319.68 32.184 ;
    END
  END qout[22]
  PIN qout[23]
    DIRECTION OUTPUT ;
    USE SIGNAL ;
    PORT
      LAYER M4 ;
        RECT  319.488 32.256 319.68 32.28 ;
    END
  END qout[23]
  PIN qout[24]
    DIRECTION OUTPUT ;
    USE SIGNAL ;
    PORT
      LAYER M4 ;
        RECT  319.488 32.352 319.68 32.376 ;
    END
  END qout[24]
  PIN qout[25]
    DIRECTION OUTPUT ;
    USE SIGNAL ;
    PORT
      LAYER M4 ;
        RECT  319.488 32.448 319.68 32.472 ;
    END
  END qout[25]
  PIN qout[26]
    DIRECTION OUTPUT ;
    USE SIGNAL ;
    PORT
      LAYER M4 ;
        RECT  319.488 32.544 319.68 32.568 ;
    END
  END qout[26]
  PIN qout[27]
    DIRECTION OUTPUT ;
    USE SIGNAL ;
    PORT
      LAYER M4 ;
        RECT  319.488 32.64 319.68 32.664 ;
    END
  END qout[27]
  PIN qout[28]
    DIRECTION OUTPUT ;
    USE SIGNAL ;
    PORT
      LAYER M4 ;
        RECT  319.488 32.736 319.68 32.76 ;
    END
  END qout[28]
  PIN qout[29]
    DIRECTION OUTPUT ;
    USE SIGNAL ;
    PORT
      LAYER M4 ;
        RECT  319.488 32.832 319.68 32.856 ;
    END
  END qout[29]
  PIN qout[2]
    DIRECTION OUTPUT ;
    USE SIGNAL ;
    PORT
      LAYER M4 ;
        RECT  319.488 30.24 319.68 30.264 ;
    END
  END qout[2]
  PIN qout[30]
    DIRECTION OUTPUT ;
    USE SIGNAL ;
    PORT
      LAYER M4 ;
        RECT  319.488 32.928 319.68 32.952 ;
    END
  END qout[30]
  PIN qout[31]
    DIRECTION OUTPUT ;
    USE SIGNAL ;
    PORT
      LAYER M4 ;
        RECT  319.488 33.024 319.68 33.048 ;
    END
  END qout[31]
  PIN qout[32]
    DIRECTION OUTPUT ;
    USE SIGNAL ;
    PORT
      LAYER M4 ;
        RECT  319.488 33.12 319.68 33.144 ;
    END
  END qout[32]
  PIN qout[33]
    DIRECTION OUTPUT ;
    USE SIGNAL ;
    PORT
      LAYER M4 ;
        RECT  319.488 33.216 319.68 33.24 ;
    END
  END qout[33]
  PIN qout[34]
    DIRECTION OUTPUT ;
    USE SIGNAL ;
    PORT
      LAYER M4 ;
        RECT  319.488 33.312 319.68 33.336 ;
    END
  END qout[34]
  PIN qout[35]
    DIRECTION OUTPUT ;
    USE SIGNAL ;
    PORT
      LAYER M4 ;
        RECT  319.488 33.408 319.68 33.432 ;
    END
  END qout[35]
  PIN qout[36]
    DIRECTION OUTPUT ;
    USE SIGNAL ;
    PORT
      LAYER M4 ;
        RECT  319.488 33.504 319.68 33.528 ;
    END
  END qout[36]
  PIN qout[37]
    DIRECTION OUTPUT ;
    USE SIGNAL ;
    PORT
      LAYER M4 ;
        RECT  319.488 33.6 319.68 33.624 ;
    END
  END qout[37]
  PIN qout[38]
    DIRECTION OUTPUT ;
    USE SIGNAL ;
    PORT
      LAYER M4 ;
        RECT  319.488 33.696 319.68 33.72 ;
    END
  END qout[38]
  PIN qout[39]
    DIRECTION OUTPUT ;
    USE SIGNAL ;
    PORT
      LAYER M4 ;
        RECT  319.488 33.792 319.68 33.816 ;
    END
  END qout[39]
  PIN qout[3]
    DIRECTION OUTPUT ;
    USE SIGNAL ;
    PORT
      LAYER M4 ;
        RECT  319.488 30.336 319.68 30.36 ;
    END
  END qout[3]
  PIN qout[40]
    DIRECTION OUTPUT ;
    USE SIGNAL ;
    PORT
      LAYER M4 ;
        RECT  319.488 33.888 319.68 33.912 ;
    END
  END qout[40]
  PIN qout[41]
    DIRECTION OUTPUT ;
    USE SIGNAL ;
    PORT
      LAYER M4 ;
        RECT  319.488 33.984 319.68 34.008 ;
    END
  END qout[41]
  PIN qout[42]
    DIRECTION OUTPUT ;
    USE SIGNAL ;
    PORT
      LAYER M4 ;
        RECT  319.488 34.08 319.68 34.104 ;
    END
  END qout[42]
  PIN qout[43]
    DIRECTION OUTPUT ;
    USE SIGNAL ;
    PORT
      LAYER M4 ;
        RECT  319.488 34.176 319.68 34.2 ;
    END
  END qout[43]
  PIN qout[44]
    DIRECTION OUTPUT ;
    USE SIGNAL ;
    PORT
      LAYER M4 ;
        RECT  319.488 34.272 319.68 34.296 ;
    END
  END qout[44]
  PIN qout[45]
    DIRECTION OUTPUT ;
    USE SIGNAL ;
    PORT
      LAYER M4 ;
        RECT  319.488 34.368 319.68 34.392 ;
    END
  END qout[45]
  PIN qout[46]
    DIRECTION OUTPUT ;
    USE SIGNAL ;
    PORT
      LAYER M4 ;
        RECT  319.488 34.464 319.68 34.488 ;
    END
  END qout[46]
  PIN qout[47]
    DIRECTION OUTPUT ;
    USE SIGNAL ;
    PORT
      LAYER M4 ;
        RECT  319.488 34.56 319.68 34.584 ;
    END
  END qout[47]
  PIN qout[48]
    DIRECTION OUTPUT ;
    USE SIGNAL ;
    PORT
      LAYER M4 ;
        RECT  319.488 34.656 319.68 34.68 ;
    END
  END qout[48]
  PIN qout[49]
    DIRECTION OUTPUT ;
    USE SIGNAL ;
    PORT
      LAYER M4 ;
        RECT  319.488 34.752 319.68 34.776 ;
    END
  END qout[49]
  PIN qout[4]
    DIRECTION OUTPUT ;
    USE SIGNAL ;
    PORT
      LAYER M4 ;
        RECT  319.488 30.432 319.68 30.456 ;
    END
  END qout[4]
  PIN qout[50]
    DIRECTION OUTPUT ;
    USE SIGNAL ;
    PORT
      LAYER M4 ;
        RECT  319.488 34.848 319.68 34.872 ;
    END
  END qout[50]
  PIN qout[51]
    DIRECTION OUTPUT ;
    USE SIGNAL ;
    PORT
      LAYER M4 ;
        RECT  319.488 34.944 319.68 34.968 ;
    END
  END qout[51]
  PIN qout[52]
    DIRECTION OUTPUT ;
    USE SIGNAL ;
    PORT
      LAYER M4 ;
        RECT  319.488 35.04 319.68 35.064 ;
    END
  END qout[52]
  PIN qout[53]
    DIRECTION OUTPUT ;
    USE SIGNAL ;
    PORT
      LAYER M4 ;
        RECT  319.488 35.136 319.68 35.16 ;
    END
  END qout[53]
  PIN qout[54]
    DIRECTION OUTPUT ;
    USE SIGNAL ;
    PORT
      LAYER M4 ;
        RECT  319.488 35.232 319.68 35.256 ;
    END
  END qout[54]
  PIN qout[55]
    DIRECTION OUTPUT ;
    USE SIGNAL ;
    PORT
      LAYER M4 ;
        RECT  319.488 35.328 319.68 35.352 ;
    END
  END qout[55]
  PIN qout[56]
    DIRECTION OUTPUT ;
    USE SIGNAL ;
    PORT
      LAYER M4 ;
        RECT  319.488 35.424 319.68 35.448 ;
    END
  END qout[56]
  PIN qout[57]
    DIRECTION OUTPUT ;
    USE SIGNAL ;
    PORT
      LAYER M4 ;
        RECT  319.488 35.52 319.68 35.544 ;
    END
  END qout[57]
  PIN qout[58]
    DIRECTION OUTPUT ;
    USE SIGNAL ;
    PORT
      LAYER M4 ;
        RECT  319.488 35.616 319.68 35.64 ;
    END
  END qout[58]
  PIN qout[59]
    DIRECTION OUTPUT ;
    USE SIGNAL ;
    PORT
      LAYER M4 ;
        RECT  319.488 35.712 319.68 35.736 ;
    END
  END qout[59]
  PIN qout[5]
    DIRECTION OUTPUT ;
    USE SIGNAL ;
    PORT
      LAYER M4 ;
        RECT  319.488 30.528 319.68 30.552 ;
    END
  END qout[5]
  PIN qout[60]
    DIRECTION OUTPUT ;
    USE SIGNAL ;
    PORT
      LAYER M4 ;
        RECT  319.488 35.808 319.68 35.832 ;
    END
  END qout[60]
  PIN qout[61]
    DIRECTION OUTPUT ;
    USE SIGNAL ;
    PORT
      LAYER M4 ;
        RECT  319.488 35.904 319.68 35.928 ;
    END
  END qout[61]
  PIN qout[62]
    DIRECTION OUTPUT ;
    USE SIGNAL ;
    PORT
      LAYER M4 ;
        RECT  319.488 36 319.68 36.024 ;
    END
  END qout[62]
  PIN qout[63]
    DIRECTION OUTPUT ;
    USE SIGNAL ;
    PORT
      LAYER M4 ;
        RECT  319.488 36.096 319.68 36.12 ;
    END
  END qout[63]
  PIN qout[64]
    DIRECTION OUTPUT ;
    USE SIGNAL ;
    PORT
      LAYER M4 ;
        RECT  319.488 36.192 319.68 36.216 ;
    END
  END qout[64]
  PIN qout[65]
    DIRECTION OUTPUT ;
    USE SIGNAL ;
    PORT
      LAYER M4 ;
        RECT  319.488 36.288 319.68 36.312 ;
    END
  END qout[65]
  PIN qout[66]
    DIRECTION OUTPUT ;
    USE SIGNAL ;
    PORT
      LAYER M4 ;
        RECT  319.488 36.384 319.68 36.408 ;
    END
  END qout[66]
  PIN qout[67]
    DIRECTION OUTPUT ;
    USE SIGNAL ;
    PORT
      LAYER M4 ;
        RECT  319.488 36.48 319.68 36.504 ;
    END
  END qout[67]
  PIN qout[68]
    DIRECTION OUTPUT ;
    USE SIGNAL ;
    PORT
      LAYER M4 ;
        RECT  319.488 36.576 319.68 36.6 ;
    END
  END qout[68]
  PIN qout[69]
    DIRECTION OUTPUT ;
    USE SIGNAL ;
    PORT
      LAYER M4 ;
        RECT  319.488 36.672 319.68 36.696 ;
    END
  END qout[69]
  PIN qout[6]
    DIRECTION OUTPUT ;
    USE SIGNAL ;
    PORT
      LAYER M4 ;
        RECT  319.488 30.624 319.68 30.648 ;
    END
  END qout[6]
  PIN qout[70]
    DIRECTION OUTPUT ;
    USE SIGNAL ;
    PORT
      LAYER M4 ;
        RECT  319.488 36.768 319.68 36.792 ;
    END
  END qout[70]
  PIN qout[71]
    DIRECTION OUTPUT ;
    USE SIGNAL ;
    PORT
      LAYER M4 ;
        RECT  319.488 36.864 319.68 36.888 ;
    END
  END qout[71]
  PIN qout[72]
    DIRECTION OUTPUT ;
    USE SIGNAL ;
    PORT
      LAYER M4 ;
        RECT  319.488 36.96 319.68 36.984 ;
    END
  END qout[72]
  PIN qout[73]
    DIRECTION OUTPUT ;
    USE SIGNAL ;
    PORT
      LAYER M4 ;
        RECT  319.488 37.056 319.68 37.08 ;
    END
  END qout[73]
  PIN qout[74]
    DIRECTION OUTPUT ;
    USE SIGNAL ;
    PORT
      LAYER M4 ;
        RECT  319.488 37.152 319.68 37.176 ;
    END
  END qout[74]
  PIN qout[75]
    DIRECTION OUTPUT ;
    USE SIGNAL ;
    PORT
      LAYER M4 ;
        RECT  319.488 37.248 319.68 37.272 ;
    END
  END qout[75]
  PIN qout[76]
    DIRECTION OUTPUT ;
    USE SIGNAL ;
    PORT
      LAYER M4 ;
        RECT  319.488 37.344 319.68 37.368 ;
    END
  END qout[76]
  PIN qout[77]
    DIRECTION OUTPUT ;
    USE SIGNAL ;
    PORT
      LAYER M4 ;
        RECT  319.488 37.44 319.68 37.464 ;
    END
  END qout[77]
  PIN qout[78]
    DIRECTION OUTPUT ;
    USE SIGNAL ;
    PORT
      LAYER M4 ;
        RECT  319.488 37.536 319.68 37.56 ;
    END
  END qout[78]
  PIN qout[79]
    DIRECTION OUTPUT ;
    USE SIGNAL ;
    PORT
      LAYER M4 ;
        RECT  319.488 37.632 319.68 37.656 ;
    END
  END qout[79]
  PIN qout[7]
    DIRECTION OUTPUT ;
    USE SIGNAL ;
    PORT
      LAYER M4 ;
        RECT  319.488 30.72 319.68 30.744 ;
    END
  END qout[7]
  PIN qout[80]
    DIRECTION OUTPUT ;
    USE SIGNAL ;
    PORT
      LAYER M4 ;
        RECT  319.488 37.728 319.68 37.752 ;
    END
  END qout[80]
  PIN qout[81]
    DIRECTION OUTPUT ;
    USE SIGNAL ;
    PORT
      LAYER M4 ;
        RECT  319.488 37.824 319.68 37.848 ;
    END
  END qout[81]
  PIN qout[82]
    DIRECTION OUTPUT ;
    USE SIGNAL ;
    PORT
      LAYER M4 ;
        RECT  319.488 37.92 319.68 37.944 ;
    END
  END qout[82]
  PIN qout[83]
    DIRECTION OUTPUT ;
    USE SIGNAL ;
    PORT
      LAYER M4 ;
        RECT  319.488 38.016 319.68 38.04 ;
    END
  END qout[83]
  PIN qout[84]
    DIRECTION OUTPUT ;
    USE SIGNAL ;
    PORT
      LAYER M4 ;
        RECT  319.488 38.112 319.68 38.136 ;
    END
  END qout[84]
  PIN qout[85]
    DIRECTION OUTPUT ;
    USE SIGNAL ;
    PORT
      LAYER M4 ;
        RECT  319.488 38.208 319.68 38.232 ;
    END
  END qout[85]
  PIN qout[86]
    DIRECTION OUTPUT ;
    USE SIGNAL ;
    PORT
      LAYER M4 ;
        RECT  319.488 38.304 319.68 38.328 ;
    END
  END qout[86]
  PIN qout[87]
    DIRECTION OUTPUT ;
    USE SIGNAL ;
    PORT
      LAYER M4 ;
        RECT  319.488 38.4 319.68 38.424 ;
    END
  END qout[87]
  PIN qout[88]
    DIRECTION OUTPUT ;
    USE SIGNAL ;
    PORT
      LAYER M4 ;
        RECT  319.488 38.496 319.68 38.52 ;
    END
  END qout[88]
  PIN qout[89]
    DIRECTION OUTPUT ;
    USE SIGNAL ;
    PORT
      LAYER M4 ;
        RECT  319.488 38.592 319.68 38.616 ;
    END
  END qout[89]
  PIN qout[8]
    DIRECTION OUTPUT ;
    USE SIGNAL ;
    PORT
      LAYER M4 ;
        RECT  319.488 30.816 319.68 30.84 ;
    END
  END qout[8]
  PIN qout[90]
    DIRECTION OUTPUT ;
    USE SIGNAL ;
    PORT
      LAYER M4 ;
        RECT  319.488 38.688 319.68 38.712 ;
    END
  END qout[90]
  PIN qout[91]
    DIRECTION OUTPUT ;
    USE SIGNAL ;
    PORT
      LAYER M4 ;
        RECT  319.488 38.784 319.68 38.808 ;
    END
  END qout[91]
  PIN qout[92]
    DIRECTION OUTPUT ;
    USE SIGNAL ;
    PORT
      LAYER M4 ;
        RECT  319.488 38.88 319.68 38.904 ;
    END
  END qout[92]
  PIN qout[93]
    DIRECTION OUTPUT ;
    USE SIGNAL ;
    PORT
      LAYER M4 ;
        RECT  319.488 38.976 319.68 39 ;
    END
  END qout[93]
  PIN qout[94]
    DIRECTION OUTPUT ;
    USE SIGNAL ;
    PORT
      LAYER M4 ;
        RECT  319.488 39.072 319.68 39.096 ;
    END
  END qout[94]
  PIN qout[95]
    DIRECTION OUTPUT ;
    USE SIGNAL ;
    PORT
      LAYER M4 ;
        RECT  319.488 39.168 319.68 39.192 ;
    END
  END qout[95]
  PIN qout[96]
    DIRECTION OUTPUT ;
    USE SIGNAL ;
    PORT
      LAYER M4 ;
        RECT  319.488 39.264 319.68 39.288 ;
    END
  END qout[96]
  PIN qout[97]
    DIRECTION OUTPUT ;
    USE SIGNAL ;
    PORT
      LAYER M4 ;
        RECT  319.488 39.36 319.68 39.384 ;
    END
  END qout[97]
  PIN qout[98]
    DIRECTION OUTPUT ;
    USE SIGNAL ;
    PORT
      LAYER M4 ;
        RECT  319.488 39.456 319.68 39.48 ;
    END
  END qout[98]
  PIN qout[99]
    DIRECTION OUTPUT ;
    USE SIGNAL ;
    PORT
      LAYER M4 ;
        RECT  319.488 39.552 319.68 39.576 ;
    END
  END qout[99]
  PIN qout[9]
    DIRECTION OUTPUT ;
    USE SIGNAL ;
    PORT
      LAYER M4 ;
        RECT  319.488 30.912 319.68 30.936 ;
    END
  END qout[9]
  PIN rst_n
    DIRECTION INPUT ;
    USE SIGNAL ;
    PORT
      LAYER M5 ;
        RECT  209.376 77.568 209.4 77.76 ;
    END
  END rst_n
  PIN VSS
    DIRECTION INOUT ;
    USE GROUND ;
    PORT
      LAYER M6 ;
        RECT  0.468 67.736 319.212 68.024 ;
        RECT  0.468 56.936 319.212 57.224 ;
        RECT  0.468 46.136 319.212 46.424 ;
        RECT  0.468 35.336 319.212 35.624 ;
        RECT  0.468 24.536 319.212 24.824 ;
        RECT  0.468 13.736 319.212 14.024 ;
        RECT  0.468 2.936 319.212 3.224 ;
        RECT  0.66 76.98 319.02 77.268 ;
        RECT  0.66 0.492 319.02 0.78 ;
    END
  END VSS
  PIN VDD
    DIRECTION INOUT ;
    USE POWER ;
    PORT
      LAYER M6 ;
        RECT  0.468 68.12 319.212 68.408 ;
        RECT  0.468 57.32 319.212 57.608 ;
        RECT  0.468 46.52 319.212 46.808 ;
        RECT  0.468 35.72 319.212 36.008 ;
        RECT  0.468 24.92 319.212 25.208 ;
        RECT  0.468 14.12 319.212 14.408 ;
        RECT  0.468 3.32 319.212 3.608 ;
        RECT  0.468 77.364 319.212 77.652 ;
        RECT  0.468 0.108 319.212 0.396 ;
    END
  END VDD
  OBS
    LAYER RVTN ;
     RECT  0 0.108 319.68 77.76 ;
    LAYER RVTP ;
     RECT  0 0.108 319.68 77.76 ;
    LAYER M1 ;
     RECT  0 0.108 319.68 77.76 ;
    LAYER M2 ;
     RECT  0 0.108 319.68 77.76 ;
    LAYER M3 ;
     RECT  0 0.108 319.68 77.76 ;
    LAYER M4 ;
     RECT  0 0.108 319.68 77.76 ;
    LAYER M5 ;
     RECT  0 0.108 319.68 77.76 ;
    LAYER M6 ;
     RECT  0 0.108 319.68 77.76 ;
    LAYER M7 ;
     RECT  0 0.108 319.68 77.76 ;
  END
END ot_hbm_accel_smh_be_eg
END LIBRARY
